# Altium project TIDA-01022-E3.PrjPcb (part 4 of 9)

## Sheet TIDA-01022-E3_LMK00304_Buffer.SchDoc: LMK00304_Buffer
size 431 x 279 mm; Date: Not shown in title block; ApprovedBy: Not shown in title block; CheckedBy: Not shown in title block; Author: Not shown in title block; CompanyName: Not shown in title block; DrawnBy: Avinash N; Engineer: Not shown in title block; Organization: Not shown in title block; Address1: Not shown in title block; Address2: Not shown in title block; Address3: Not shown in title block; Address4: Not shown in title block; DocumentNumber: 1; Revision: Use project parameter SCH_Rev; SheetNumber: 12; SheetTotal: 26; PageSetup: Record=PageOptions¦CenterHorizontal=True¦CenterVertical=True¦PrintScale=1.00¦XCorrection=1.00¦YCorrection=1.00¦PrintKind=0¦BorderSize=5000000¦LeftOffset=0¦BottomOffset=0¦Orientation=2¦PaperLength=1000¦PaperWidth=1000¦Scale=100¦PaperSource=15¦PrintQuality=600¦MediaType=1¦DitherType=10¦PaperKind=Letter¦PrintScaleMode=1

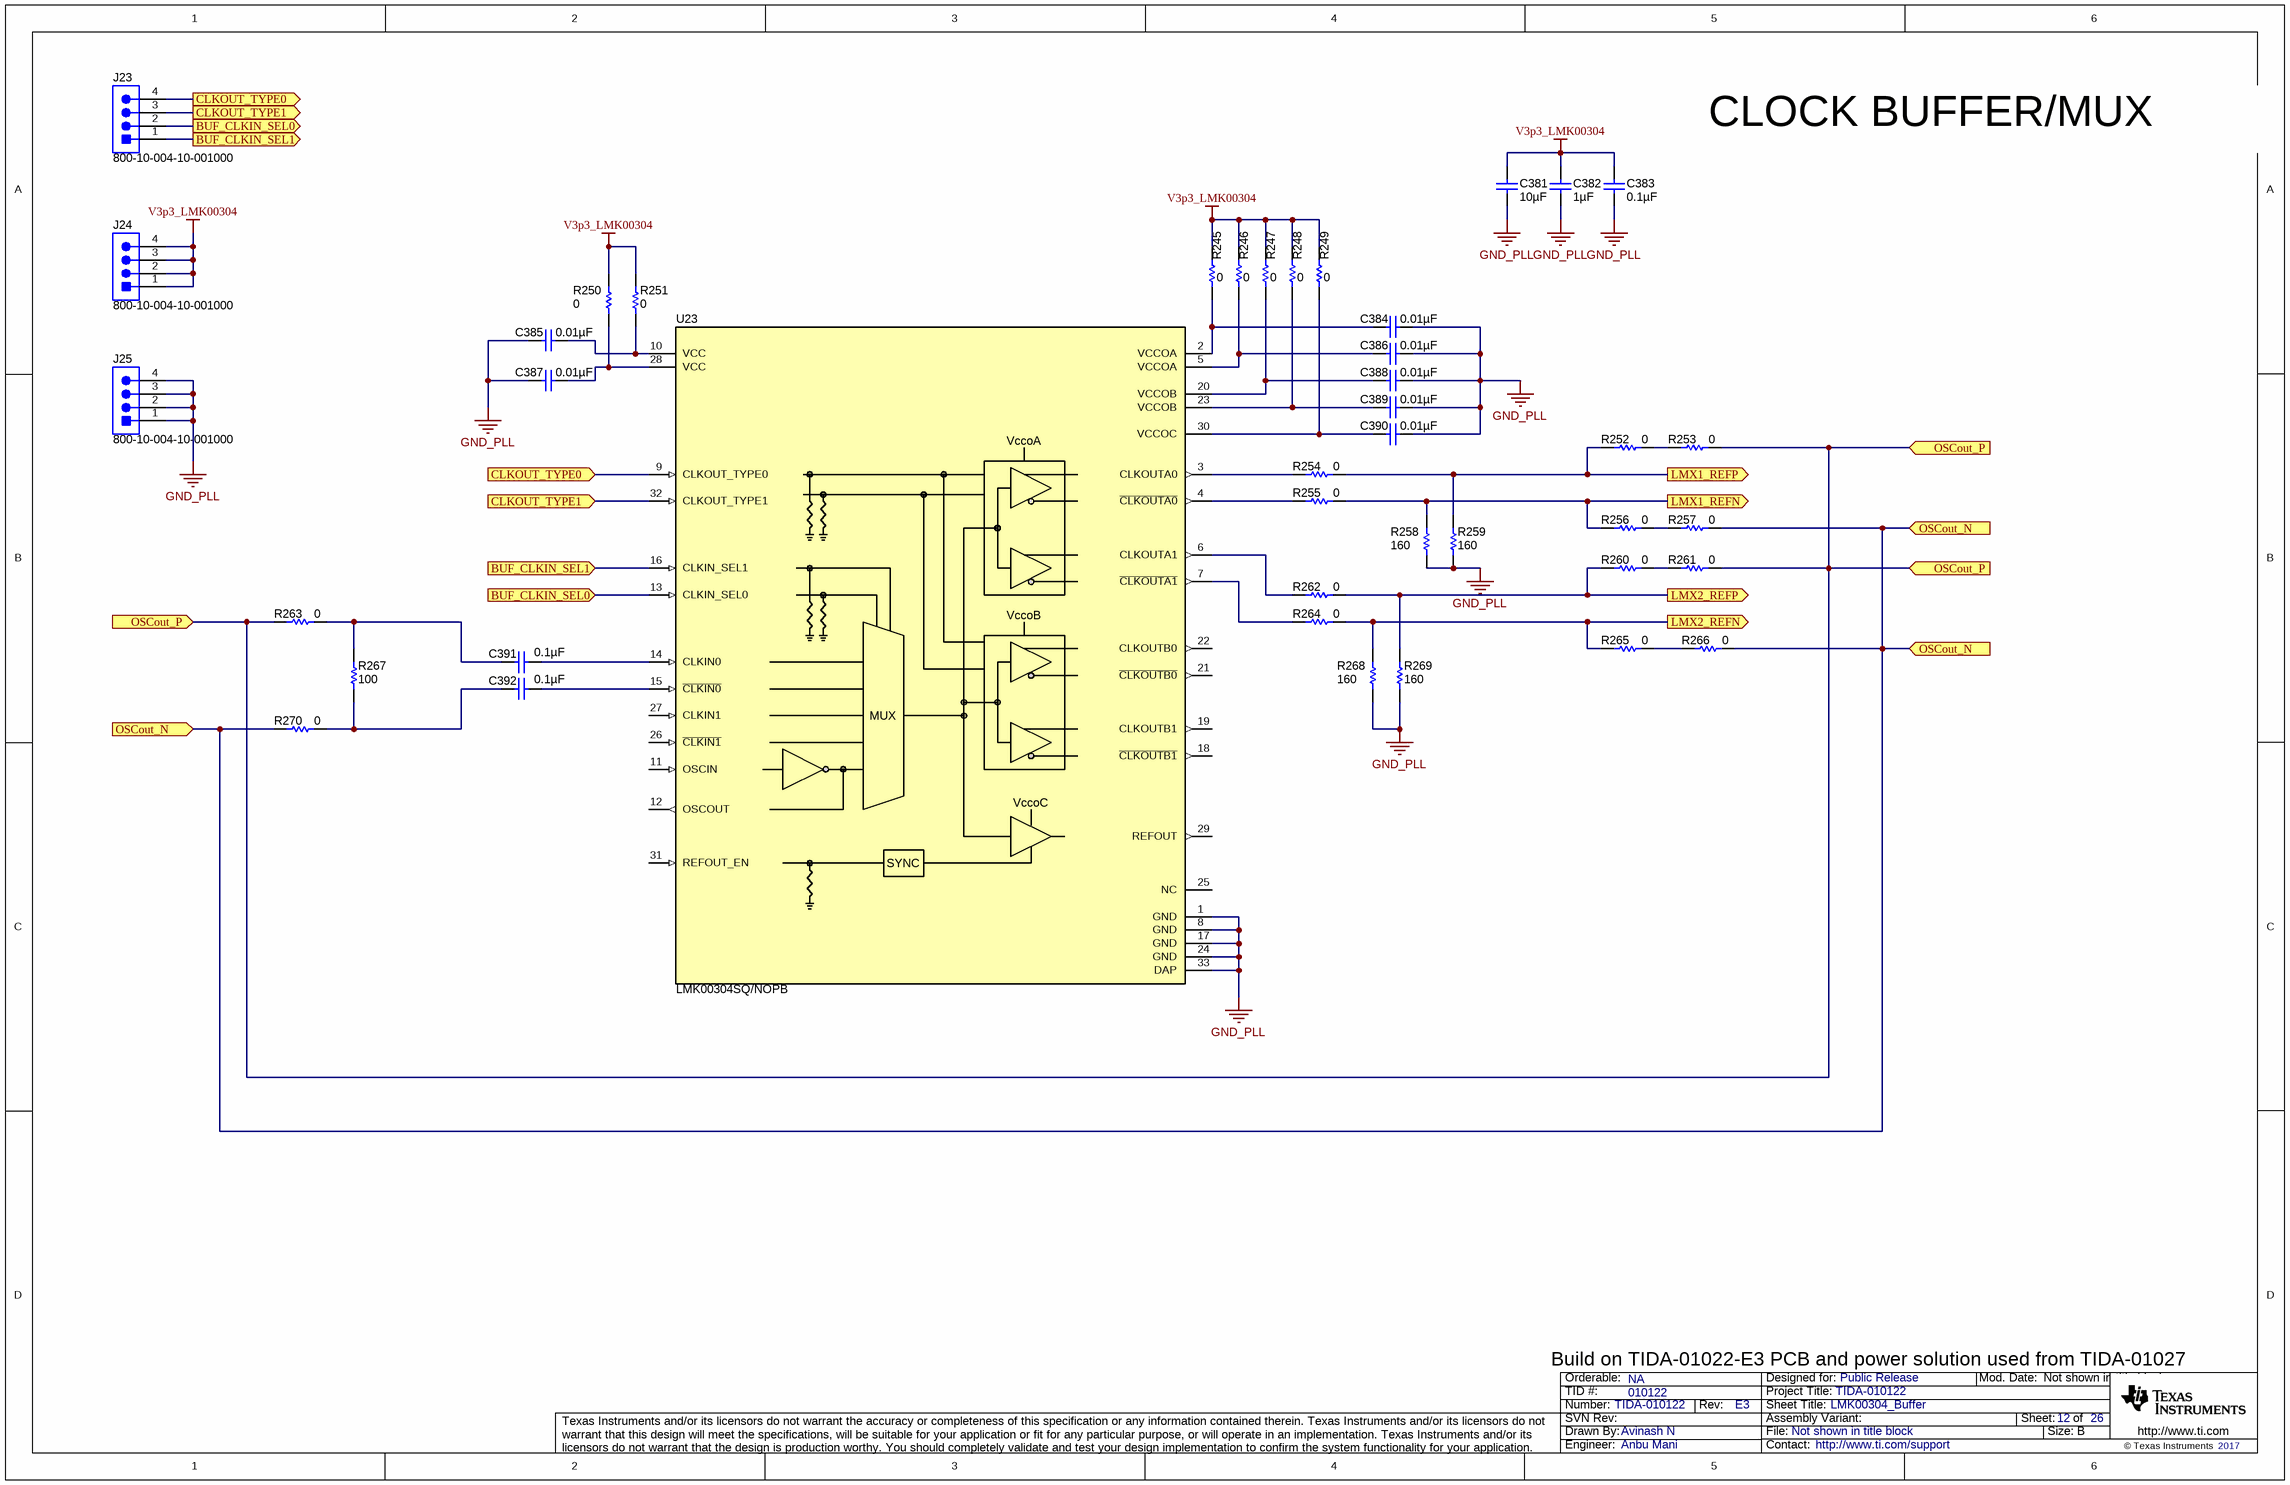
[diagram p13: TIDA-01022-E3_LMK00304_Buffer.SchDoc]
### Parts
C381  ValueDisplayed: 10µF  [0603]  (hidden comment: EMK107BBJ106MA-T)
C382  ValueDisplayed: 1µF  [0402]  (hidden comment: C1005X7S1A105K050BC)
C383  ValueDisplayed: 0.1µF  [0402]  (hidden comment: GRM155R71C104KA88D)
C384  ValueDisplayed: 0.01µF  [0402]  (hidden comment: GRM155R71E103KA01D)
C385  ValueDisplayed: 0.01µF  [0402]  (hidden comment: GRM155R71E103KA01D)
C386  ValueDisplayed: 0.01µF  [0402]  (hidden comment: GRM155R71E103KA01D)
C387  ValueDisplayed: 0.01µF  [0402]  (hidden comment: GRM155R71E103KA01D)
C388  ValueDisplayed: 0.01µF  [0402]  (hidden comment: GRM155R71E103KA01D)
C389  ValueDisplayed: 0.01µF  [0402]  (hidden comment: GRM155R71E103KA01D)
C390  ValueDisplayed: 0.01µF  [0402]  (hidden comment: GRM155R71E103KA01D)
C391  ValueDisplayed: 0.1µF  [0402]  (hidden comment: C1005X7R1E104M050BB)
C392  ValueDisplayed: 0.1µF  [0402]  (hidden comment: C1005X7R1E104M050BB)
J23  800-10-004-10-001000  [Mill-Max_800-10-004-10-001000]
J24  800-10-004-10-001000  [Mill-Max_800-10-004-10-001000]
J25  800-10-004-10-001000  [Mill-Max_800-10-004-10-001000]
R245  ValueDisplayed: 0  [0402]  (hidden comment: CRCW04020000Z0ED)
R246  ValueDisplayed: 0  [0402]  (hidden comment: CRCW04020000Z0ED)
R247  ValueDisplayed: 0  [0402]  (hidden comment: CRCW04020000Z0ED)
R248  ValueDisplayed: 0  [0402]  (hidden comment: CRCW04020000Z0ED)
R249  ValueDisplayed: 0  [0402]  (hidden comment: CRCW04020000Z0ED)
R250  ValueDisplayed: 0  [0402]  (hidden comment: CRCW04020000Z0ED)
R251  ValueDisplayed: 0  [0402]  (hidden comment: CRCW04020000Z0ED)
R252  ValueDisplayed: 0  [0402]  (hidden comment: CRCW04020000Z0ED)
R253  ValueDisplayed: 0  [0402]  (hidden comment: CRCW04020000Z0ED)
R254  ValueDisplayed: 0  [0402]  (hidden comment: CRCW04020000Z0ED)
R255  ValueDisplayed: 0  [0402]  (hidden comment: CRCW04020000Z0ED)
R256  ValueDisplayed: 0  [0402]  (hidden comment: CRCW04020000Z0ED)
R257  ValueDisplayed: 0  [0402]  (hidden comment: CRCW04020000Z0ED)
R258  ValueDisplayed: 160  [0402]  (hidden comment: CRCW0402160RJNED)
R259  ValueDisplayed: 160  [0402]  (hidden comment: CRCW0402160RJNED)
R260  ValueDisplayed: 0  [0402]  (hidden comment: CRCW04020000Z0ED)
R261  ValueDisplayed: 0  [0402]  (hidden comment: CRCW04020000Z0ED)
R262  ValueDisplayed: 0  [0402]  (hidden comment: CRCW04020000Z0ED)
R263  ValueDisplayed: 0  [0402]  (hidden comment: CRCW04020000Z0ED)
R264  ValueDisplayed: 0  [0402]  (hidden comment: CRCW04020000Z0ED)
R265  ValueDisplayed: 0  [0402]  (hidden comment: CRCW04020000Z0ED)
R266  ValueDisplayed: 0  [0402]  (hidden comment: CRCW04020000Z0ED)
R267  ValueDisplayed: 100  [0402]  (hidden comment: CRCW0402100RFKED)
R268  ValueDisplayed: 160  [0402]  (hidden comment: CRCW0402160RJNED)
R269  ValueDisplayed: 160  [0402]  (hidden comment: CRCW0402160RJNED)
R270  ValueDisplayed: 0  [0402]  (hidden comment: CRCW04020000Z0ED)
U23  LMK00304SQ/NOPB  [RTV0032A]

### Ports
BUF_CLKIN_SEL0 (in), BUF_CLKIN_SEL0 (out), BUF_CLKIN_SEL1 (in), BUF_CLKIN_SEL1 (out), CLKOUT_TYPE0 (in), CLKOUT_TYPE0 (out), CLKOUT_TYPE1 (in), CLKOUT_TYPE1 (out), LMX1_REFN (out), LMX1_REFP (out), LMX2_REFN (out), LMX2_REFP (out), OSCout_N (in), OSCout_P (in)

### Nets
GND_PLL: C381.2 C382.2 C383.2 C384.2 C385.1 C386.2 C387.1 C388.2 C389.2 C390.2 J25.1 J25.2 J25.3 J25.4 R258.1 R259.1 R268.1 R269.1 U23.1(GND) U23.8(GND) U23.17(GND) U23.24(GND) U23.33(DAP)  [project net DGND]
V3p3_LMK00304: C381.1 C382.1 C383.1 J24.1 J24.2 J24.3 J24.4 R245.2 R246.2 R247.2 R248.2 R249.2 R250.2 R251.2
BUF_CLKIN_SEL0: J23.2 U23.13(CLKIN_SEL0) ; port BUF_CLKIN_SEL0
BUF_CLKIN_SEL1: J23.1 U23.16(CLKIN_SEL1) ; port BUF_CLKIN_SEL1
CLKOUT_TYPE0: J23.4 U23.9(CLKOUT_TYPE0) ; port CLKOUT_TYPE0
CLKOUT_TYPE1: J23.3 U23.32(CLKOUT_TYPE1) ; port CLKOUT_TYPE1
LMX1_REFN: R255.2 R256.1 R258.2 ; port LMX1_REFN
LMX1_REFP: R252.1 R254.2 R259.2 ; port LMX1_REFP
LMX2_REFN: R264.2 R265.1 R268.2 ; port LMX2_REFN
LMX2_REFP: R260.1 R262.2 R269.2 ; port LMX2_REFP
OSCout_N: R257.2 R266.2 R270.1 ; port OSCout_N
OSCout_P: R253.2 R261.2 R263.1 ; port OSCout_P
NetC384_1: C384.1 R245.1 U23.2(VCCOA)
NetC385_2: C385.2 R251.1 U23.10(VCC)
NetC386_1: C386.1 R246.1 U23.5(VCCOA)
NetC387_2: C387.2 R250.1 U23.28(VCC)
NetC388_1: C388.1 R247.1 U23.20(VCCOB)
NetC389_1: C389.1 R248.1 U23.23(VCCOB)
NetC390_1: C390.1 R249.1 U23.30(VCCOC)
NetC391_1: C391.1 R263.2 R267.2
NetC391_2: C391.2 U23.14(CLKIN0)
NetC392_1: C392.1 R267.1 R270.2
NetC392_2: C392.2 U23.15(~{CLKIN0})
NetR252_2: R252.2 R253.1
NetR254_1: R254.1 U23.3(CLKOUTA0)
NetR255_1: R255.1 U23.4(~{CLKOUTA0})
NetR256_2: R256.2 R257.1
NetR260_2: R260.2 R261.1
NetR262_1: R262.1 U23.6(CLKOUTA1)
NetR264_1: R264.1 U23.7(~{CLKOUTA1})
NetR265_2: R265.2 R266.1

Not connected (* = marked no-connect by the designer): U23 11(OSCIN) 12(OSCOUT) 18(~{CLKOUTB1}) 19(CLKOUTB1) 21(~{CLKOUTB0}) 22(CLKOUTB0) 25(NC) 26(~{CLKIN1}) 27(CLKIN1) 29(REFOUT) 31(REFOUT_EN)

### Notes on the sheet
- CLOCK BUFFER/MUX
- Build on TIDA-01022-E3 PCB and power solution used from TIDA-01027

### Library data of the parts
C381 = EMK107BBJ106MA-T: CAP, CERM, 10 µF, 16 V, +/- 20%, X5R, 0603; Manufacturer: Taiyo Yuden; Polarized: N; CompType: Capacitor; Value: 10uF; U/M: EA; Cap_F: 0.00001; Tolerance_%: 20; Value1: Unknown; VDC_V: 16; Value2: 16V; TaMin_C: -55; TaMax_C: 85; SizeArea_mm2: 1.28; SizeAreaWB_mm2: 4.68; SizeX_mm: 1.6; SizeY_mm: 0.8; SizeZ_mm: 1; AEC Category: Q200
C382 = C1005X7S1A105K050BC: CAP, CERM, 1 µF, 10 V, +/- 10%, X7S, 0402; Manufacturer: TDK; Polarized: N; CompType: Capacitor; Value: 1uF; U/M: EA; Cap_F: 0.000001; Tolerance_%: 10; ESR_ohm: 0.011416; Value1: 0.011416 ohm; Value2: 10V; IRMS_A: 1.483; TaMin_C: -55; TaMax_C: 125; SizeArea_mm2: 0.5; SizeAreaWB_mm2: 3; SizeX_mm: 1; SizeZ_mm: 0.6; AEC Category: Q200
C383 = GRM155R71C104KA88D: CAP, CERM, 0.1 µF, 16 V, +/- 10%, X7R, 0402; Manufacturer: MuRata; Polarized: N; CompType: Capacitor; Value: 0.1uF; U/M: EA; Cap_F: 0.0000001; Tolerance_%: 10; Value1: Unknown; VDC_V: 16; Value2: 16V; TaMin_C: -55; TaMax_C: 125; SizeArea_mm2: 0.5; SizeAreaWB_mm2: 3; SizeX_mm: 1; SizeZ_mm: 0.6; AEC Category: Q200
C384-C390 = GRM155R71E103KA01D: CAP, CERM, 0.01 µF, 25 V, +/- 10%, X7R, 0402; Manufacturer: MuRata; Polarized: N; CompType: Capacitor; Value: 0.01uF; U/M: EA; Cap_F: 0.00000001; Tolerance_%: 10; Value1: Unknown; VDC_V: 25; Value2: 25V; TaMin_C: -55; TaMax_C: 125; SizeArea_mm2: 0.5; SizeAreaWB_mm2: 3; SizeX_mm: 1; SizeZ_mm: 0.6; AEC Category: Q200
C391 C392 = C1005X7R1E104M050BB: CAP, CERM, 0.1 µF, 25 V, +/- 20%, X7R, 0402; Manufacturer: TDK; Polarized: N; TaMax_C: 125; TaMin_C: -55; Tolerance_%: 20; VDC_V: 25; Cap_F: 0.0000001; CompType: Capacitor; Value: 0.1uF; Value1: Unknown; Value2: 25V; U/M: EA; SizeArea_mm2: 0.5; SizeAreaWB_mm2: 3; SizeX_mm: 1; SizeZ_mm: 0.6; AEC Category: Q200
J23-J25 = 800-10-004-10-001000: Header, 100mil, 4x1, TH; Manufacturer: Mill-Max; SymbolCreator: a0412235
R245-R257 R260-R266 R270 = CRCW04020000Z0ED: RES, 0, 5%, 0.063 W, 0402; Manufacturer: Vishay-Dale; CompType: Resistor; Value: 0; Value_Code: 0000; Tolerance_%: 5; Power_W: 0.063; Value2: 0.063W; VDC_V: 50; TempCo: 200 ppm/C; SizeArea_mm2: 0.5; SizeX_mm: 1; SizeZ_mm: 0.6; EIA_Code: E24; U/M: EA; AEC Category: Q200
R258 R259 R268 R269 = CRCW0402160RJNED: RES, 160, 5%, 0.063 W, 0402; Manufacturer: Vishay-Dale; CompType: Resistor; Value: 160; Value_Code: 160R; Tolerance_%: 5; Power_W: 0.063; Value2: 0.063W; VDC_V: 50; TempCo: 200 ppm/C; SizeArea_mm2: 0.5; SizeX_mm: 1; SizeZ_mm: 0.6; EIA_Code: E24; U/M: EA; AEC Category: Q200
R267 = CRCW0402100RFKED: RES, 100, 1%, 0.063 W, 0402; Manufacturer: Vishay-Dale; CompType: Resistor; Value: 100; Value_Code: 100R; Tolerance_%: 1; Power_W: 0.063; Value2: 0.063W; VDC_V: 50; TempCo: 100 ppm/C; SizeArea_mm2: 0.5; SizeZ_mm: 0.6; EIA_Code: E96; U/M: EA; AEC Category: Q200
U23 = LMK00304SQ/NOPB: 3.1-GHz Differential Clock Buffer/Level Translator, RTV0032A (WQFN-32); Manufacturer: Texas Instruments; SymbolCreator: a0411947; SizeArea_mm2: 25; SizeAreaWB_mm2: 49; SizeX_mm: 5; SizeZ_mm: 0.8; CompType: IC; U/M: EA

## Sheet TIDA-01022-E3_LMK0482x.SchDoc: LMK0482x
size 431 x 279 mm; Date: Not shown in title block; ApprovedBy: Not shown in title block; CheckedBy: Not shown in title block; Author: Not shown in title block; CompanyName: Not shown in title block; DrawnBy: Avinash N; Engineer: Not shown in title block; Organization: Not shown in title block; Address1: Not shown in title block; Address2: Not shown in title block; Address3: Not shown in title block; Address4: Not shown in title block; DocumentNumber: 1; Revision: Use project parameter SCH_Rev; SheetNumber: 13; SheetTotal: 26; PageSetup: Record=PageOptions¦CenterHorizontal=True¦CenterVertical=True¦PrintScale=1.00¦XCorrection=1.00¦YCorrection=1.00¦PrintKind=0¦BorderSize=5000000¦LeftOffset=0¦BottomOffset=0¦Orientation=2¦PaperLength=1000¦PaperWidth=1000¦Scale=100¦PaperSource=15¦PrintQuality=600¦MediaType=1¦DitherType=10¦PaperKind=Letter¦PrintScaleMode=1

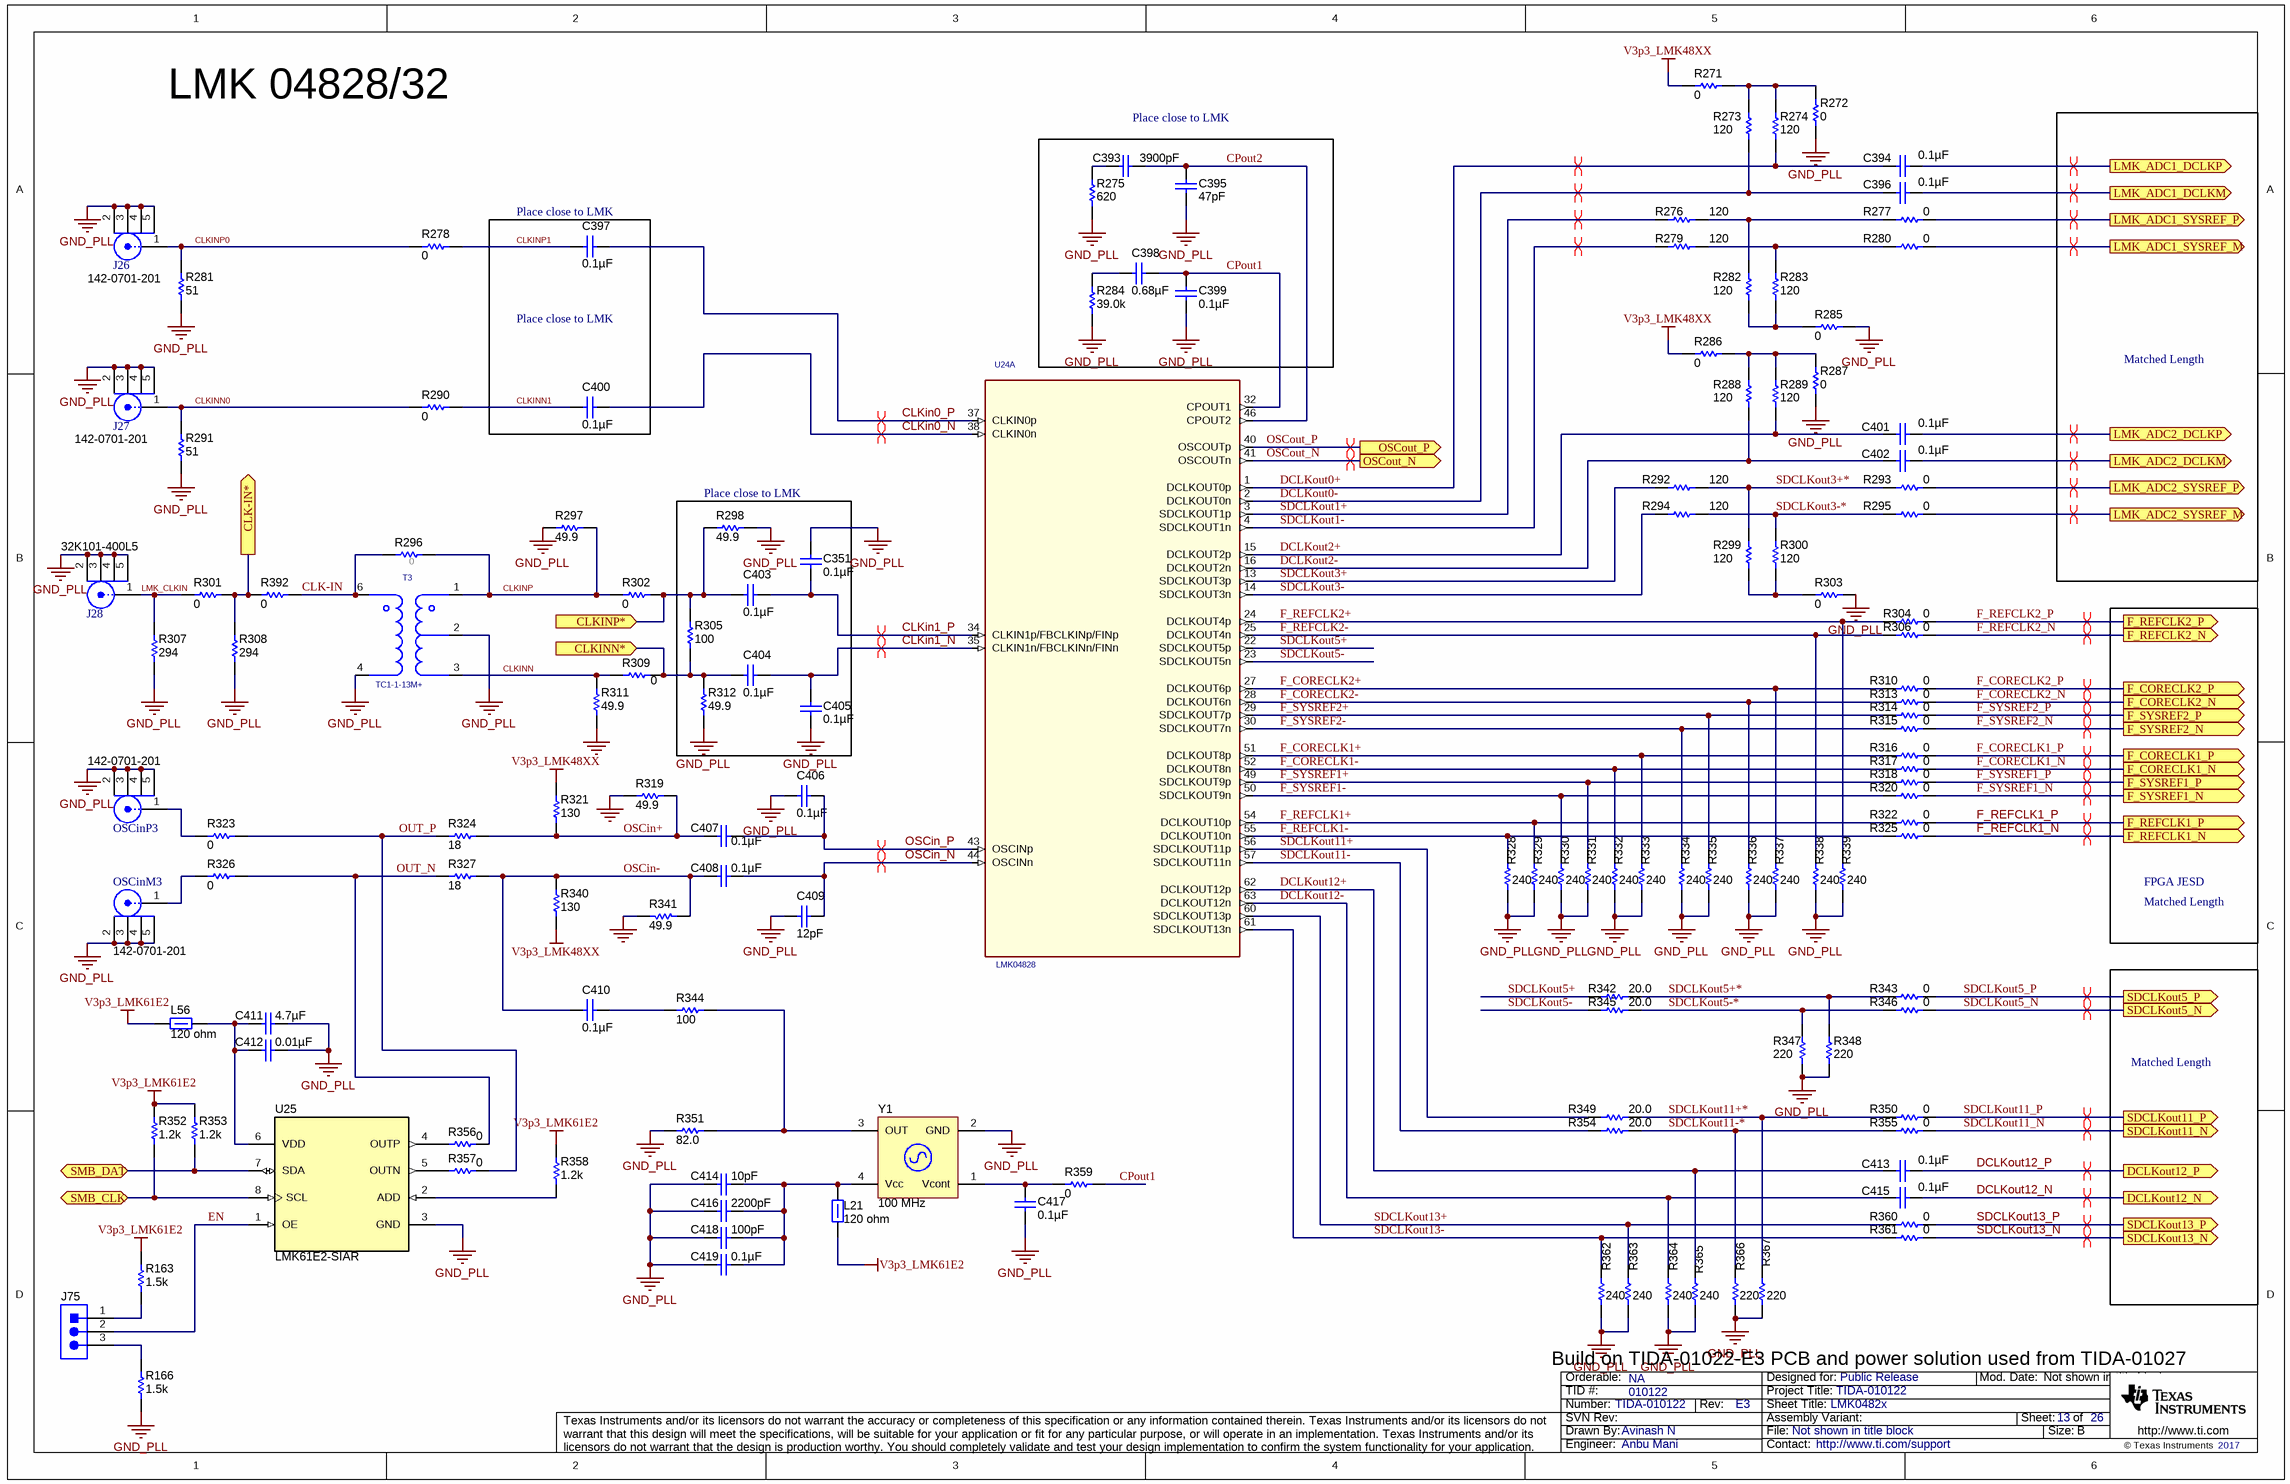
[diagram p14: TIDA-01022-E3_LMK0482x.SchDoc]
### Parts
C351  ValueDisplayed: 0.1µF  [0201_033]  (hidden comment: GRM033R60J104KE19D)
C393  ValueDisplayed: 3900pF  [0201]  (hidden comment: 0201ZD392KAT2A)
C394  ValueDisplayed: 0.1µF  [0402]  (hidden comment: C1005X7R1E104M050BB)
C395  ValueDisplayed: 47pF  [0201_033]  (hidden comment: GRM0335C1E470JA01D)
C396  ValueDisplayed: 0.1µF  [0402]  (hidden comment: C1005X7R1E104M050BB)
C397  ValueDisplayed: 0.1µF  [0201_033]  (hidden comment: GRM033R60J104KE19D)
C398  ValueDisplayed: 0.68µF  [0402]  (hidden comment: C1005X5R1A684K050BB)
C399  ValueDisplayed: 0.1µF  [0402]  (hidden comment: C1005X7R1E104M050BB)
C400  ValueDisplayed: 0.1µF  [0201_033]  (hidden comment: GRM033R60J104KE19D)
C401  ValueDisplayed: 0.1µF  [0402]  (hidden comment: C1005X7R1E104M050BB)
C402  ValueDisplayed: 0.1µF  [0402]  (hidden comment: C1005X7R1E104M050BB)
C403  ValueDisplayed: 0.1µF  [0201_033]  (hidden comment: GRM033R60J104KE19D)
C404  ValueDisplayed: 0.1µF  [0201_033]  (hidden comment: GRM033R60J104KE19D)
C405  ValueDisplayed: 0.1µF  [0201_033]  (hidden comment: GRM033R60J104KE19D)
C406  ValueDisplayed: 0.1µF  [0402]  (hidden comment: C1005X7R1E104M050BB)
C407  ValueDisplayed: 0.1µF  [0402]  (hidden comment: C1005X7R1E104M050BB)
C408  ValueDisplayed: 0.1µF  [0402]  (hidden comment: C1005X7R1E104M050BB)
C409  ValueDisplayed: 12pF  [0402]  (hidden comment: C0402C120J3GACAUTO)
C410  ValueDisplayed: 0.1µF  [0402]  (hidden comment: C1005X7R1E104M050BB)
C411  ValueDisplayed: 4.7µF  [0402]  (hidden comment: C1005X5R0J475M050BC)
C412  ValueDisplayed: 0.01µF  [0402]  (hidden comment: GRM155R71E103KA01D)
C413  ValueDisplayed: 0.1µF  [0402]  (hidden comment: C1005X7R1E104M050BB)
C414  ValueDisplayed: 10pF  [0402]  (hidden comment: GRM1555C1H100JA01D)
C415  ValueDisplayed: 0.1µF  [0402]  (hidden comment: C1005X7R1E104M050BB)
C416  ValueDisplayed: 2200pF  [0402]  (hidden comment: GRM155R71E222KA01D)
C417  ValueDisplayed: 0.1µF  [0402]  (hidden comment: C1005X7R1E104M050BB)
C418  ValueDisplayed: 100pF  [0402]  (hidden comment: 04025A101FAT2A)
C419  ValueDisplayed: 0.1µF  [0402]  (hidden comment: C1005X7R1E104M050BB)
J26  142-0701-201  [Johnson_142-0701-20x]
J27  142-0701-201  [Johnson_142-0701-20x]
J28  32K101-400L5  [Rosenberger_32K101-400L5]
J75  800-10-003-10-001000  [Mill-Max_800-10-003-10-001000]  (value not drawn)
L21  ValueDisplayed: 120 ohm  [0603]  (hidden comment: BLM18SG121TN1D)
L56  ValueDisplayed: 120 ohm  [0603]  (hidden comment: BLM18SG121TN1D)
OSCinM3  142-0701-201  [Johnson_142-0701-20x]
OSCinP3  142-0701-201  [Johnson_142-0701-20x]
R163  ValueDisplayed: 1.5k  [0402]  (hidden comment: CRCW04021K50JNED)
R166  ValueDisplayed: 1.5k  [0402]  (hidden comment: CRCW04021K50JNED)
R271  ValueDisplayed: 0  [0402]  (hidden comment: CRCW04020000Z0ED)
R272  ValueDisplayed: 0  [0402]  (hidden comment: CRCW04020000Z0ED)
R273  ValueDisplayed: 120  [0402]  (hidden comment: CRCW0402120RJNED)
R274  ValueDisplayed: 120  [0402]  (hidden comment: CRCW0402120RJNED)
R275  ValueDisplayed: 620  [0201]  (hidden comment: RC0201FR-07620RL)
R276  ValueDisplayed: 120  [0402]  (hidden comment: CRCW0402120RJNED)
R277  ValueDisplayed: 0  [0402]  (hidden comment: CRCW04020000Z0ED)
R278  ValueDisplayed: 0  [0201]  (hidden comment: CRCW02010000Z0ED)
R279  ValueDisplayed: 120  [0402]  (hidden comment: CRCW0402120RJNED)
R280  ValueDisplayed: 0  [0402]  (hidden comment: CRCW04020000Z0ED)
R281  ValueDisplayed: 51  [0201]  (hidden comment: RC0201JR-0751RL)
R282  ValueDisplayed: 120  [0402]  (hidden comment: CRCW0402120RJNED)
R283  ValueDisplayed: 120  [0402]  (hidden comment: CRCW0402120RJNED)
R284  ValueDisplayed: 39.0k  [0201]  (hidden comment: RC0201FR-0739KL)
R285  ValueDisplayed: 0  [0402]  (hidden comment: CRCW04020000Z0ED)
R286  ValueDisplayed: 0  [0402]  (hidden comment: CRCW04020000Z0ED)
R287  ValueDisplayed: 0  [0402]  (hidden comment: CRCW04020000Z0ED)
R288  ValueDisplayed: 120  [0402]  (hidden comment: CRCW0402120RJNED)
R289  ValueDisplayed: 120  [0402]  (hidden comment: CRCW0402120RJNED)
R290  ValueDisplayed: 0  [0201]  (hidden comment: CRCW02010000Z0ED)
R291  ValueDisplayed: 51  [0201]  (hidden comment: RC0201JR-0751RL)
R292  ValueDisplayed: 120  [0402]  (hidden comment: CRCW0402120RJNED)
R293  ValueDisplayed: 0  [0402]  (hidden comment: CRCW04020000Z0ED)
R294  ValueDisplayed: 120  [0402]  (hidden comment: CRCW0402120RJNED)
R295  ValueDisplayed: 0  [0402]  (hidden comment: CRCW04020000Z0ED)
R296  ValueDisplayed: 0  [0603]  (hidden comment: CRCW06030000Z0EA)
R297  ValueDisplayed: 49.9  [0201]  (hidden comment: CRCW020149R9FKED)
R298  ValueDisplayed: 49.9  [0201]  (hidden comment: CRCW020149R9FKED)
R299  ValueDisplayed: 120  [0402]  (hidden comment: CRCW0402120RJNED)
R300  ValueDisplayed: 120  [0402]  (hidden comment: CRCW0402120RJNED)
R301  ValueDisplayed: 0  [0201_adc]  (hidden comment: CRCW02010000Z0ED)
R302  ValueDisplayed: 0  [0201]  (hidden comment: CRCW02010000Z0ED)
R303  ValueDisplayed: 0  [0402]  (hidden comment: CRCW04020000Z0ED)
R304  ValueDisplayed: 0  [0402]  (hidden comment: CRCW04020000Z0ED)
R305  ValueDisplayed: 100  [0201]  (hidden comment: ERJ-1GEF1000C)
R306  ValueDisplayed: 0  [0402]  (hidden comment: CRCW04020000Z0ED)
R307  ValueDisplayed: 294  [0201_adc]  (hidden comment: RC0201FR-07294RL)
R308  ValueDisplayed: 294  [0201_adc]  (hidden comment: RC0201FR-07294RL)
R309  ValueDisplayed: 0  [0201]  (hidden comment: CRCW02010000Z0ED)
R310  ValueDisplayed: 0  [0402]  (hidden comment: CRCW04020000Z0ED)
R311  ValueDisplayed: 49.9  [0201]  (hidden comment: CRCW020149R9FKED)
R312  ValueDisplayed: 49.9  [0201]  (hidden comment: CRCW020149R9FKED)
R313  ValueDisplayed: 0  [0402]  (hidden comment: CRCW04020000Z0ED)
R314  ValueDisplayed: 0  [0402]  (hidden comment: CRCW04020000Z0ED)
R315  ValueDisplayed: 0  [0402]  (hidden comment: CRCW04020000Z0ED)
R316  ValueDisplayed: 0  [0402]  (hidden comment: CRCW04020000Z0ED)
R317  ValueDisplayed: 0  [0402]  (hidden comment: CRCW04020000Z0ED)
R318  ValueDisplayed: 0  [0402]  (hidden comment: CRCW04020000Z0ED)
R319  ValueDisplayed: 49.9  [0402]  (hidden comment: CRCW040249R9FKED)
R320  ValueDisplayed: 0  [0402]  (hidden comment: CRCW04020000Z0ED)
R321  ValueDisplayed: 130  [0402]  (hidden comment: CRCW0402130RFKED)
R322  ValueDisplayed: 0  [0402]  (hidden comment: CRCW04020000Z0ED)
R323  ValueDisplayed: 0  [0402]  (hidden comment: CRCW04020000Z0ED)
R324  ValueDisplayed: 18  [0402]  (hidden comment: CRCW040218R0JNED)
R325  ValueDisplayed: 0  [0402]  (hidden comment: CRCW04020000Z0ED)
R326  ValueDisplayed: 0  [0402]  (hidden comment: CRCW04020000Z0ED)
R327  ValueDisplayed: 18  [0402]  (hidden comment: CRCW040218R0JNED)
R328  ValueDisplayed: 240  [0402]  (hidden comment: CRCW0402240RJNED)
R329  ValueDisplayed: 240  [0402]  (hidden comment: CRCW0402240RJNED)
R330  ValueDisplayed: 240  [0402]  (hidden comment: CRCW0402240RJNED)
R331  ValueDisplayed: 240  [0402]  (hidden comment: CRCW0402240RJNED)
R332  ValueDisplayed: 240  [0402]  (hidden comment: CRCW0402240RJNED)
R333  ValueDisplayed: 240  [0402]  (hidden comment: CRCW0402240RJNED)
R334  ValueDisplayed: 240  [0402]  (hidden comment: CRCW0402240RJNED)
R335  ValueDisplayed: 240  [0402]  (hidden comment: CRCW0402240RJNED)
R336  ValueDisplayed: 240  [0402]  (hidden comment: CRCW0402240RJNED)
R337  ValueDisplayed: 240  [0402]  (hidden comment: CRCW0402240RJNED)
R338  ValueDisplayed: 240  [0402]  (hidden comment: CRCW0402240RJNED)
R339  ValueDisplayed: 240  [0402]  (hidden comment: CRCW0402240RJNED)
R340  ValueDisplayed: 130  [0402]  (hidden comment: CRCW0402130RFKED)
R341  ValueDisplayed: 49.9  [0402]  (hidden comment: CRCW040249R9FKED)
R342  ValueDisplayed: 20.0  [0402]  (hidden comment: CRCW040220R0FKED)
R343  ValueDisplayed: 0  [0402]  (hidden comment: CRCW04020000Z0ED)
R344  ValueDisplayed: 100  [0402]  (hidden comment: CRCW0402100RFKED)
R345  ValueDisplayed: 20.0  [0402]  (hidden comment: CRCW040220R0FKED)
R346  ValueDisplayed: 0  [0402]  (hidden comment: CRCW04020000Z0ED)
R347  ValueDisplayed: 220  [0402]  (hidden comment: CRCW0402220RJNED)
R348  ValueDisplayed: 220  [0402]  (hidden comment: CRCW0402220RJNED)
R349  ValueDisplayed: 20.0  [0402]  (hidden comment: CRCW040220R0FKED)
R350  ValueDisplayed: 0  [0402]  (hidden comment: CRCW04020000Z0ED)
R351  ValueDisplayed: 82.0  [0603]  (hidden comment: RC0603FR-0782RL)
R352  ValueDisplayed: 1.2k  [0402]  (hidden comment: CRCW04021K20JNED)
R353  ValueDisplayed: 1.2k  [0402]  (hidden comment: CRCW04021K20JNED)
R354  ValueDisplayed: 20.0  [0402]  (hidden comment: CRCW040220R0FKED)
R355  ValueDisplayed: 0  [0402]  (hidden comment: CRCW04020000Z0ED)
R356  ValueDisplayed: 0  [0402]  (hidden comment: CRCW04020000Z0ED)
R357  ValueDisplayed: 0  [0402]  (hidden comment: CRCW04020000Z0ED)
R358  ValueDisplayed: 1.2k  [0402]  (hidden comment: CRCW04021K20JNED)
R359  ValueDisplayed: 0  [0402]  (hidden comment: CRCW04020000Z0ED)
R360  ValueDisplayed: 0  [0402]  (hidden comment: CRCW04020000Z0ED)
R361  ValueDisplayed: 0  [0402]  (hidden comment: CRCW04020000Z0ED)
R362  ValueDisplayed: 240  [0402]  (hidden comment: CRCW0402240RJNED)
R363  ValueDisplayed: 240  [0402]  (hidden comment: CRCW0402240RJNED)
R364  ValueDisplayed: 240  [0402]  (hidden comment: CRCW0402240RJNED)
R365  ValueDisplayed: 240  [0402]  (hidden comment: CRCW0402240RJNED)
R366  ValueDisplayed: 220  [0402]  (hidden comment: CRCW0402220RJNED)
R367  ValueDisplayed: 220  [0402]  (hidden comment: CRCW0402220RJNED)
R392  ValueDisplayed: 0  [0201_ADC]  (hidden comment: CRCW02010000Z0ED)
T3  TC1-1-13M+  [TFMR_5_150x150_50]
U24  LMK04828  [NKD0064A]  (part A of 2)
U25  LMK61E2-SIAR  [SIA0008B]
Y1  Frequency: 100 MHz  [OSC_CVHD-950-4]  (hidden comment: CVHD-950-100.000)

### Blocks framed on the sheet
Place close to LMK: C393 C395 C398 C399 R275 R284
Place close to LMK: C351 C403-C405 R298 R305 R312

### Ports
CLK-IN* (out), CLKINN* (in), CLKINP* (in), DCLKout12_N (out), DCLKout12_P (out), F_CORECLK1_N (out), F_CORECLK1_P (out), F_CORECLK2_N (out), F_CORECLK2_P (out), F_REFCLK1_N (out), F_REFCLK1_P (out), F_REFCLK2_N (out), F_REFCLK2_P (out), F_SYSREF1_N (out), F_SYSREF1_P (out), F_SYSREF2_N (out), F_SYSREF2_P (out), LMK_ADC1_DCLKM (out), LMK_ADC1_DCLKP (out), LMK_ADC1_SYSREF_M (out), LMK_ADC1_SYSREF_P (out), LMK_ADC2_DCLKM (out), LMK_ADC2_DCLKP (out), LMK_ADC2_SYSREF_M (out), LMK_ADC2_SYSREF_P (out), OSCout_N (out), OSCout_P (out), SDCLKout5_N (out), SDCLKout5_P (out), SDCLKout11_N (out), SDCLKout11_P (out), SDCLKout13_N (out), SDCLKout13_P (out), SMB_CLK (bidir), SMB_DAT (bidir)

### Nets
GND_PLL: C351.1 C395.2 C399.1 C405.1 C406.1 C409.1 C411.1 C412.1 C414.1 C416.1 C417.1 C418.1 C419.1 J26.2 J26.3 J26.4 J26.5 J27.2 J27.3 J27.4 J27.5 J28.2 J28.3 J28.4 J28.5 OSCinM3.2 OSCinM3.3 OSCinM3.4 OSCinM3.5 OSCinP3.2 OSCinP3.3 OSCinP3.4 OSCinP3.5 R166.1 R272.1 R275.1 R281.1 R284.1 R285.2 R287.1 R291.1 R297.1 R298.2 R303.2 R307.1 R308.1 R311.1 R312.1 R319.1 R328.1 R329.1 R330.1 R331.1 R332.1 R333.1 R334.1 R335.1 R336.1 R337.1 R338.1 R339.1 R341.1 R347.1 R348.1 R351.1 R362.1 R363.1 R364.1 R365.1 R366.1 R367.1 T3.2(secondary_ct) T3.4(primary) U25.3(GND) Y1.2(GND)  [project net DGND]
V3p3_LMK48XX: R271.2 R286.2 R321.1 R340.1
V3p3_LMK61E2: L21.2 L56.1 R163.2 R352.2 R353.2 R358.1
CLK-IN: R296.1 R392.2 T3.6(primary_dot)
CLK-IN*: R301.2 R308.2 R392.1 ; port CLK-IN*
CLKin0_N: C400.2 U24.38(CLKIN0n)
CLKin0_P: C397.2 U24.37(CLKIN0p)
CLKin1_N: C404.2 C405.2 U24.35(CLKIN1n/FBCLKINn/FINn)
CLKin1_P: C351.2 C403.2 U24.34(CLKIN1p/FBCLKINp/FINp)
CLKINN: R309.1 R311.2 T3.3(secondary)
CLKINN0: J27.1 R290.1 R291.2
CLKINN1: C400.1 R290.2
CLKINN*: C404.1 R305.1 R309.2 R312.2 ; port CLKINN*
CLKINP: R296.2 R297.2 R302.1 T3.1(secondary_dot)
CLKINP0: J26.1 R278.1 R281.2
CLKINP1: C397.1 R278.2
CLKINP*: C403.1 R298.1 R302.2 R305.2 ; port CLKINP*
CPout1: C398.2 C399.2 R359.2 U24.32(CPOUT1)
CPout2: C393.1 C395.1 U24.46(CPOUT2)
DCLKout0+: C394.1 R274.2 U24.1(DCLKOUT0p)
DCLKout0-: C396.1 R273.2 U24.2(DCLKOUT0n)
DCLKout2+: C401.1 R289.2 U24.15(DCLKOUT2p)
DCLKout2-: C402.1 R288.2 U24.16(DCLKOUT2n)
DCLKout12+: C413.1 R365.2 U24.62(DCLKOUT12p)
DCLKout12-: C415.1 R364.2 U24.63(DCLKOUT12n)
DCLKout12_N: C415.2 ; port DCLKout12_N
DCLKout12_P: C413.2 ; port DCLKout12_P
EN: J75.2 U25.1(OE)
F_CORECLK1+: R316.1 R333.2 U24.51(DCLKOUT8p)
F_CORECLK1-: R317.1 R332.2 U24.52(DCLKOUT8n)
F_CORECLK1_N: R317.2 ; port F_CORECLK1_N
F_CORECLK1_P: R316.2 ; port F_CORECLK1_P
F_CORECLK2+: R310.1 R337.2 U24.27(DCLKOUT6p)
F_CORECLK2-: R313.1 R336.2 U24.28(DCLKOUT6n)
F_CORECLK2_N: R313.2 ; port F_CORECLK2_N
F_CORECLK2_P: R310.2 ; port F_CORECLK2_P
F_REFCLK1+: R322.1 R329.2 U24.54(DCLKOUT10p)
F_REFCLK1-: R325.1 R328.2 U24.55(DCLKOUT10n)
F_REFCLK1_N: R325.2 ; port F_REFCLK1_N
F_REFCLK1_P: R322.2 ; port F_REFCLK1_P
F_REFCLK2+: R304.1 R339.2 U24.24(DCLKOUT4p)
F_REFCLK2-: R306.1 R338.2 U24.25(DCLKOUT4n)
F_REFCLK2_N: R306.2 ; port F_REFCLK2_N
F_REFCLK2_P: R304.2 ; port F_REFCLK2_P
F_SYSREF1+: R318.1 R331.2 U24.49(SDCLKOUT9p)
F_SYSREF1-: R320.1 R330.2 U24.50(SDCLKOUT9n)
F_SYSREF1_N: R320.2 ; port F_SYSREF1_N
F_SYSREF1_P: R318.2 ; port F_SYSREF1_P
F_SYSREF2+: R314.1 R335.2 U24.29(SDCLKOUT7p)
F_SYSREF2-: R315.1 R334.2 U24.30(SDCLKOUT7n)
F_SYSREF2_N: R315.2 ; port F_SYSREF2_N
F_SYSREF2_P: R314.2 ; port F_SYSREF2_P
LMK_ADC1_DCLKM: C396.2 ; port LMK_ADC1_DCLKM
LMK_ADC1_DCLKP: C394.2 ; port LMK_ADC1_DCLKP
LMK_ADC1_SYSREF_M: R280.2 ; port LMK_ADC1_SYSREF_M
LMK_ADC1_SYSREF_P: R277.2 ; port LMK_ADC1_SYSREF_P
LMK_ADC2_DCLKM: C402.2 ; port LMK_ADC2_DCLKM
LMK_ADC2_DCLKP: C401.2 ; port LMK_ADC2_DCLKP
LMK_ADC2_SYSREF_M: R295.2 ; port LMK_ADC2_SYSREF_M
LMK_ADC2_SYSREF_P: R293.2 ; port LMK_ADC2_SYSREF_P
LMK_CLKIN: J28.1 R301.1 R307.2
OSCin+: C407.2 R319.2 R321.2 R324.2
OSCin-: C408.2 C410.2 R327.2 R340.2 R341.2
OSCin_N: C408.1 C409.2 U24.44(OSCINn)
OSCin_P: C406.2 C407.1 U24.43(OSCINp)
OSCout_N: U24.41(OSCOUTn) ; port OSCout_N
OSCout_P: U24.40(OSCOUTp) ; port OSCout_P
OUT_N: R326.1 R327.1 R356.2
OUT_P: R323.1 R324.1 R357.2
SDCLKout1+: R276.2 U24.3(SDCLKOUT1p)
SDCLKout1-: R279.2 U24.4(SDCLKOUT1n)
SDCLKout3+: R292.2 U24.13(SDCLKOUT3p)
SDCLKout3+*: R292.1 R293.1 R299.2
SDCLKout3-: R294.2 U24.14(SDCLKOUT3n)
SDCLKout3-*: R294.1 R295.1 R300.2
SDCLKout5+: R342.2 U24.22(SDCLKOUT5p)
SDCLKout5+*: R342.1 R343.1 R348.2
SDCLKout5-: R345.2 U24.23(SDCLKOUT5n)
SDCLKout5-*: R345.1 R346.1 R347.2
SDCLKout5_N: R346.2 ; port SDCLKout5_N
SDCLKout5_P: R343.2 ; port SDCLKout5_P
SDCLKout11+: R349.2 U24.56(SDCLKOUT11p)
SDCLKout11+*: R349.1 R350.1 R367.2
SDCLKout11-: R354.2 U24.57(SDCLKOUT11n)
SDCLKout11-*: R354.1 R355.1 R366.2
SDCLKout11_N: R355.2 ; port SDCLKout11_N
SDCLKout11_P: R350.2 ; port SDCLKout11_P
SDCLKout13+: R360.1 R363.2 U24.60(SDCLKOUT13p)
SDCLKout13-: R361.1 R362.2 U24.61(SDCLKOUT13n)
SDCLKout13_N: R361.2 ; port SDCLKout13_N
SDCLKout13_P: R360.2 ; port SDCLKout13_P
SMB_CLK: R352.1 U25.8(SCL) ; port SMB_CLK
SMB_DAT: R353.1 U25.7(SDA) ; port SMB_DAT
NetC393_2: C393.2 R275.2
NetC398_1: C398.1 R284.2
NetC410_1: C410.1 R344.1
NetC411_2: C411.2 C412.2 L56.2 U25.6(VDD)
NetC414_2: C414.2 C416.2 C418.2 C419.2 L21.1 Y1.4(Vcc)
NetC417_2: C417.2 R359.1 Y1.1(Vcont)
NetJ75_1: J75.1 R163.1
NetJ75_3: J75.3 R166.2
NetOSCinM3_1: OSCinM3.1 R326.2
NetOSCinP3_1: OSCinP3.1 R323.2
NetR271_1: R271.1 R272.2 R273.1 R274.1
NetR276_1: R276.1 R277.1 R282.2
NetR279_1: R279.1 R280.1 R283.2
NetR282_1: R282.1 R283.1 R285.1
NetR286_1: R286.1 R287.2 R288.1 R289.1
NetR299_1: R299.1 R300.1 R303.1
NetR344_2: R344.2 R351.2 Y1.3(OUT)
NetR356_1: R356.1 U25.4(OUTP)
NetR357_1: R357.1 U25.5(OUTN)
NetR358_2: R358.2 U25.2(ADD)

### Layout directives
differential pair: CLKin0_N, CLKin0_P, CLKin1_N, CLKin1_P, DCLKout0+, DCLKout0-, DCLKout12_N, DCLKout12_P, F_CORECLK1_N, F_CORECLK1_P, F_CORECLK2_N, F_CORECLK2_P, F_REFCLK1_N, F_REFCLK1_P, F_REFCLK2_N, F_REFCLK2_P, F_SYSREF1_N, F_SYSREF1_P, F_SYSREF2_N, F_SYSREF2_P, LMK_ADC1_DCLKM, LMK_ADC1_DCLKP, LMK_ADC1_SYSREF_M, LMK_ADC1_SYSREF_P, LMK_ADC2_DCLKM, LMK_ADC2_DCLKP, LMK_ADC2_SYSREF_M, LMK_ADC2_SYSREF_P, OSCin_N, OSCin_P, OSCout_N, OSCout_P, SDCLKout1+, SDCLKout1-, SDCLKout5_N, SDCLKout5_P, SDCLKout11_N, SDCLKout11_P, SDCLKout13_N, SDCLKout13_P

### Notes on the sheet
- LMK 04828/32
- (near C397) Place close to LMK
- Place close to LMK
- Matched Length
- FPGA JESD
- Build on TIDA-01022-E3 PCB and power solution used from TIDA-01027

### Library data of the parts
C351 C397 C400 C403-C405 = GRM033R60J104KE19D: CAP, CERM, 0.1 µF, 6.3 V, +/- 10%, X5R, 0201; Manufacturer: MuRata; Polarized: N; CompType: Capacitor; Value: 0.1uF; U/M: EA; Cap_F: 0.0000001; Tolerance_%: 10; Value1: Unknown; VDC_V: 6.3; Value2: 6.3V; TaMin_C: -55; TaMax_C: 85; Cap_Case: 0201; SizeArea_mm2: 0.18; SizeAreaWB_mm2: 2.08; SizeX_mm: 0.6; SizeY_mm: 0.3; SizeZ_mm: 0.33; AEC Category: Q200
C393 = 0201ZD392KAT2A: CAP, CERM, 3900 pF, 10 V, +/- 10%, X5R, 0201; Manufacturer: AVX; Polarized: N; CompType: Capacitor; Value: 3900pF; U/M: EA; Cap_F: 0.0000000039; Tolerance_%: 10; Value1: Unknown; Value2: 10V; TaMin_C: -55; TaMax_C: 85; SizeArea_mm2: 0.18; SizeAreaWB_mm2: 2.08; SizeX_mm: 0.6; SizeY_mm: 0.3; SizeZ_mm: 0.26; AEC Category: Q200
C394 C396 C399 C401 C402 C406-C408 C410 C413 C415 C417 C419 = C1005X7R1E104M050BB: as C391 on sheet TIDA-01022-E3_LMK00304_Buffer
C395 = GRM0335C1E470JA01D: CAP, CERM, 47 pF, 25 V, +/- 5%, C0G/NP0, 0201; Manufacturer: MuRata; Polarized: N; CompType: Capacitor; Value: 47pF; U/M: EA; Cap_F: 0.000000000047; Tolerance_%: 5; Value1: Unknown; VDC_V: 25; Value2: 25V; TaMin_C: -55; TaMax_C: 125; Cap_Case: 0201; SizeArea_mm2: 0.18; SizeAreaWB_mm2: 2.08; SizeX_mm: 0.6; SizeY_mm: 0.3; SizeZ_mm: 0.33; AEC Category: Q200
C398 = C1005X5R1A684K050BB: CAP, CERM, 0.68 µF, 10 V, +/- 10%, X5R, 0402; Manufacturer: TDK; Polarized: N; CompType: Capacitor; Value: 0.68uF; U/M: EA; Cap_F: 0.00000068; Tolerance_%: 10; Value1: Unknown; Value2: 10V; TaMin_C: -55; TaMax_C: 85; SizeArea_mm2: 0.5; SizeAreaWB_mm2: 3; SizeX_mm: 1; SizeZ_mm: 0.6; AEC Category: Q200
C409 = C0402C120J3GACAUTO: CAP, CERM, 12 pF, 25 V, +/- 5%, C0G/NP0, AEC-Q200 Grade 1, 0402; Manufacturer: Kemet; Polarized: N; CompType: Capacitor; Value: 12pF; U/M: EA; Cap_F: 0.000000000012; Tolerance_%: 5; Value1: Unknown; VDC_V: 25; Value2: 25V; TaMin_C: -55; TaMax_C: 125; SizeArea_mm2: 0.5; SizeAreaWB_mm2: 3; SizeX_mm: 1; SizeZ_mm: 0.6; AEC Category: Q200; AEC Qualified: Y
C411 = C1005X5R0J475M050BC: CAP, CERM, 4.7 µF, 6.3 V, +/- 20%, X5R, 0402; Manufacturer: TDK; Polarized: N; CompType: Capacitor; Value: 4.7uF; U/M: EA; Cap_F: 0.0000047; Tolerance_%: 20; Value1: Unknown; VDC_V: 6.3; Value2: 6.3V; TaMin_C: -55; TaMax_C: 85; SizeArea_mm2: 0.5; SizeAreaWB_mm2: 3; SizeX_mm: 1; SizeZ_mm: 0.6; AEC Category: Q200
C412 = GRM155R71E103KA01D: as C384-C390 on sheet TIDA-01022-E3_LMK00304_Buffer
C414 = GRM1555C1H100JA01D: CAP, CERM, 10 pF, 50 V, +/- 5%, C0G/NP0, 0402; Manufacturer: MuRata; Polarized: N; CompType: Capacitor; Value: 10pF; U/M: EA; Cap_F: 0.00000000001; Tolerance_%: 5; Value1: Unknown; VDC_V: 50; Value2: 50V; TaMin_C: -55; TaMax_C: 125; SizeArea_mm2: 0.5; SizeAreaWB_mm2: 3; SizeX_mm: 1; SizeZ_mm: 0.6; AEC Category: Q200
C416 = GRM155R71E222KA01D: CAP, CERM, 2200 pF, 25 V, +/- 10%, X7R, 0402; Manufacturer: MuRata; Polarized: N; CompType: Capacitor; Value: 2200pF; U/M: EA; Cap_F: 0.0000000022; Tolerance_%: 10; Value1: Unknown; VDC_V: 25; Value2: 25V; TaMin_C: -55; TaMax_C: 125; SizeArea_mm2: 0.5; SizeAreaWB_mm2: 3; SizeX_mm: 1; SizeZ_mm: 0.6; AEC Category: Q200
C418 = 04025A101FAT2A: CAP, CERM, 100 pF, 50 V, +/- 1%, C0G/NP0, 0402; Manufacturer: AVX; Polarized: N; CompType: Capacitor; Value: 100pF; U/M: EA; Cap_F: 0.0000000001; Tolerance_%: 1; Value1: Unknown; VDC_V: 50; Value2: 50V; TaMin_C: -55; TaMax_C: 125; SizeArea_mm2: 0.5; SizeAreaWB_mm2: 3; SizeZ_mm: 0.6; AEC Category: Q200
J26 J27 OSCinM3 OSCinP3 = 142-0701-201: Connector, TH, SMA; Manufacturer: Emerson Network Power; SymbolCreator: X0208326
J28 = CMP-0077743-1: SMA, 50 Ohm, Gold, TH; Manufacturer: Rosenberger; Gender: Female; Voltage_V: 480V
J75 = 800-10-003-10-001000: Header, 100mil, 3x1, TH; Manufacturer: Mill-Max; SymbolCreator: a0799628
L21 L56 = BLM18SG121TN1D: Ferrite Bead, 120 ohm @ 100 MHz, 3 A, 0603; Manufacturer: MuRata; Value: 120 ohm; Imax_A: 3; DCR_ohm: 0.025; Value1: 0.025 ohm; Value2: 3A; SizeAreaWB_mm2: 4.68; SizeArea_mm2: 1.28; SizeX_mm: 1.6; SizeY_mm: 0.8; SizeZ_mm: 1; ZTyp@100MHz_Ohm: 120
R163 R166 = CRCW04021K50JNED: RES, 1.5 k, 5%, 0.063 W, 0402; Manufacturer: Vishay-Dale; CompType: Resistor; Value: 1.5k; Res_ohm: 1500; Value_Code: 1k50; Tolerance_%: 5; Power_W: 0.063; Value2: 0.063W; VDC_V: 50; TempCo: 200 ppm/C; SizeArea_mm2: 0.5; SizeX_mm: 1; SizeZ_mm: 0.6; EIA_Code: E24; U/M: EA; AEC Category: Q200
R271 R272 R277 R280 R285-R287 R293 R295 R303 R304 R306 R310 R313-R318 R320 R322 R325 R343 R346 R350 R355 R359-R361 = CRCW04020000Z0ED: as R245-R257 on sheet TIDA-01022-E3_LMK00304_Buffer
R273 R274 R276 R279 R282 R283 R288 R289 R292 R294 R299 R300 = CRCW0402120RJNED: RES, 120, 5%, 0.063 W, 0402; Manufacturer: Vishay-Dale; CompType: Resistor; Value: 120; Value_Code: 120R; Tolerance_%: 5; Power_W: 0.063; Value2: 0.063W; VDC_V: 50; TempCo: 200 ppm/C; SizeArea_mm2: 0.5; SizeX_mm: 1; SizeZ_mm: 0.6; EIA_Code: E24; U/M: EA; AEC Category: Q200
R275 = RC0201FR-07620RL: RES, 620, 1%, 0.05 W, 0201; Manufacturer: Yageo America; CompType: Resistor; Value: 620; Value_Code: 620R; Tolerance_%: 1; Power_W: 0.05; Value2: 0.05W; VDC_V: 25; TempCo: 200 ppm/C; SizeArea_mm2: 0.18; SizeX_mm: 0.6; SizeY_mm: 0.3; SizeZ_mm: 0.26; U/M: EA; AEC Category: Q200; AEC Qualified: N
R278 R290 R301 R302 R309 R392 = CRCW02010000Z0ED: RES, 0, 5%, 0.05 W, 0201; Manufacturer: Vishay-Dale; CompType: Resistor; Tolerance_%: 5; Power_W: 0.05; Value: 0; U/M: EA; Value_Code: 0000; Value2: 0.05W; EIA_Code: E24; TempCo: ppm/C; SizeArea_mm2: 0.18; SizeX_mm: 0.6; SizeY_mm: 0.3; SizeZ_mm: 0.26; AEC Category: Q200; AEC Qualified: N
R281 R291 = RC0201JR-0751RL: RES, 51, 5%, 0.05 W, 0201; Manufacturer: Yageo America; CompType: Resistor; Value: 51; Value_Code: 51R0; Tolerance_%: 5; Power_W: 0.05; Value2: 0.05W; VDC_V: 25; TempCo: 200 ppm/C; SizeArea_mm2: 0.18; SizeX_mm: 0.6; SizeY_mm: 0.3; SizeZ_mm: 0.26; EIA_Code: E24; U/M: EA; AEC Category: Q200; AEC Qualified: N
R284 = RC0201FR-0739KL: RES, 39.0 k, 1%, 0.05 W, 0201; Manufacturer: Yageo America; CompType: Resistor; Value: 39.0k; Res_ohm: 39000; Value_Code: 39k0; Tolerance_%: 1; Power_W: 0.05; Value2: 0.05W; VDC_V: 25; TempCo: 200 ppm/C; SizeArea_mm2: 0.18; SizeX_mm: 0.6; SizeY_mm: 0.3; SizeZ_mm: 0.26; U/M: EA; AEC Category: Q200; AEC Qualified: N
R296 = CRCW06030000Z0EA: RES, 0, 5%, 0.1 W, 0603; Manufacturer: Vishay-Dale; CompType: Resistor; Tolerance_%: 5; VDC_V: 75; Power_W: 0.1; Value: 0; U/M: EA; Value_Code: 0000; Value2: 0.1W; EIA_Code: E24; TempCo: 200 ppm/C; SizeArea_mm2: 1.28; SizeX_mm: 1.6; SizeY_mm: 0.8; SizeZ_mm: 1; AEC Category: Q200
R297 R298 R311 R312 = CRCW020149R9FKED: RES, 49.9, 1%, 0.05 W, 0201; Manufacturer: Vishay-Dale; CompType: Resistor; Value: 49.9; Value_Code: 49R9; Tolerance_%: 1; Power_W: 0.05; Value2: 0.05W; VDC_V: 30; TempCo: 100 ppm/C; SizeArea_mm2: 0.18; SizeX_mm: 0.6; SizeY_mm: 0.3; SizeZ_mm: 0.26; EIA_Code: E96; U/M: EA; AEC Category: Q200; AEC Qualified: N
R305 = ERJ-1GEF1000C: RES, 100, 1%, 0.05 W, 0201; Manufacturer: Panasonic; CompType: Resistor; Value: 100; Value_Code: 100R; Tolerance_%: 1; Power_W: 0.05; Value2: 0.05W; VDC_V: 25; TempCo: 200 ppm/C; SizeArea_mm2: 0.18; SizeX_mm: 0.6; SizeY_mm: 0.3; SizeZ_mm: 0.26; EIA_Code: E96; U/M: EA; AEC Category: Q200
R307 R308 = RC0201FR-07294RL: RES, 294, 1%, 0.05 W, 0201; Manufacturer: Yageo America; CompType: Resistor; Value: 294; Value_Code: 294R; Tolerance_%: 1; Power_W: 0.05; Value2: 0.05W; VDC_V: 25; TempCo: 200 ppm/C; SizeArea_mm2: 0.18; SizeX_mm: 0.6; SizeY_mm: 0.3; SizeZ_mm: 0.26; EIA_Code: E96; U/M: EA; AEC Category: Q200; AEC Qualified: N
R319 R341 = CRCW040249R9FKED: RES, 49.9, 1%, 0.063 W, 0402; Manufacturer: Vishay-Dale; CompType: Resistor; Value: 49.9; Value_Code: 49R9; Tolerance_%: 1; Power_W: 0.063; Value2: 0.063W; VDC_V: 50; TempCo: 100 ppm/C; EIA_Code: E96; U/M: EA; AEC Category: Q200
R321 R340 = CRCW0402130RFKED: RES, 130, 1%, 0.063 W, 0402; Manufacturer: Vishay-Dale; CompType: Resistor; Value: 130; Value_Code: 130R; Tolerance_%: 1; Power_W: 0.063; Value2: 0.063W; VDC_V: 50; TempCo: 100 ppm/C; SizeArea_mm2: 0.5; SizeZ_mm: 0.6; EIA_Code: E96; U/M: EA; AEC Category: Q200
R323 R326 R356 R357 = CRCW04020000Z0ED: RES, 0, 5%, 0.063 W, 0402; Manufacturer: Vishay-Dale; CompType: Resistor; Value: 0; Value_Code: 0000; Tolerance_%: 5; Power_W: 0.063; Value2: 0.063W; VDC_V: 50; TempCo: 200 ppm/C; EIA_Code: E24; U/M: EA; AEC Category: Q200
R324 R327 = CRCW040218R0JNED: RES, 18, 5%, 0.063 W, 0402; Manufacturer: Vishay-Dale; CompType: Resistor; Value: 18; Value_Code: 18R0; Tolerance_%: 5; Power_W: 0.063; Value2: 0.063W; VDC_V: 50; TempCo: 200 ppm/C; EIA_Code: E24; U/M: EA; AEC Category: Q200
R328-R339 R362-R365 = CRCW0402240RJNED: RES, 240, 5%, 0.063 W, 0402; Manufacturer: Vishay-Dale; CompType: Resistor; Value: 240; Value_Code: 240R; Tolerance_%: 5; Power_W: 0.063; Value2: 0.063W; VDC_V: 50; TempCo: 200 ppm/C; SizeArea_mm2: 0.5; SizeX_mm: 1; SizeZ_mm: 0.6; EIA_Code: E24; U/M: EA; AEC Category: Q200
R342 R345 R349 R354 = CRCW040220R0FKED: RES, 20.0, 1%, 0.063 W, 0402; Manufacturer: Vishay-Dale; CompType: Resistor; Value: 20.0; Res_ohm: 20; Value_Code: 20R0; Tolerance_%: 1; Power_W: 0.063; Value2: 0.063W; VDC_V: 50; TempCo: 100 ppm/C; SizeArea_mm2: 0.5; SizeZ_mm: 0.6; EIA_Code: E96; U/M: EA; AEC Category: Q200
R344 = CRCW0402100RFKED: RES, 100, 1%, 0.063 W, 0402; Manufacturer: Vishay-Dale; CompType: Resistor; Value: 100; Value_Code: 100R; Tolerance_%: 1; Power_W: 0.063; Value2: 0.063W; VDC_V: 50; TempCo: 100 ppm/C; EIA_Code: E96; U/M: EA; AEC Category: Q200; SizeArea_mm2: 0.5; SizeZ_mm: 0.6
R347 R348 R366 R367 = CRCW0402220RJNED: RES, 220, 5%, 0.063 W, 0402; Manufacturer: Vishay-Dale; CompType: Resistor; Value: 220; Value_Code: 220R; Tolerance_%: 5; Power_W: 0.063; Value2: 0.063W; VDC_V: 50; TempCo: 200 ppm/C; SizeArea_mm2: 0.5; SizeX_mm: 1; SizeZ_mm: 0.6; EIA_Code: E24; U/M: EA; AEC Category: Q200
R351 = RC0603FR-0782RL: RES, 82.0, 1%, 0.1 W, 0603; Manufacturer: Yageo America; CompType: Resistor; Value: 82.0; Res_ohm: 82; Value_Code: 82R0; Tolerance_%: 1; Power_W: 0.1; Value2: 0.1W; VDC_V: 150; TempCo: 200 ppm/C; SizeArea_mm2: 1.28; SizeX_mm: 1.6; SizeY_mm: 0.8; U/M: EA; AEC Category: Q200
R352 R353 R358 = CRCW04021K20JNED: RES, 1.2 k, 5%, 0.063 W, 0402; Manufacturer: Vishay-Dale; CompType: Resistor; Value: 1.2k; Res_ohm: 1200; Value_Code: 1k20; Tolerance_%: 5; Power_W: 0.063; Value2: 0.063W; VDC_V: 50; TempCo: 200 ppm/C; EIA_Code: E24; U/M: EA; AEC Category: Q200; SizeArea_mm2: 0.5; SizeX_mm: 1; SizeZ_mm: 0.6
T3 = TFMR_5_TC1-1-13M+: RF Transformer; Manufacturer: Mini-Circuits
U24 = LMK04828: LMK04828BISQE/NOPB; Manufacturer: Texas Instruments
U25 = LMK61E2-SIAR: Ultra-Low Jitter Programmable Oscillator with Internal EEPROM, SIA0008B; Alternate PartNumber: LMK61E2-SIAT; Manufacturer: Texas Instruments; SymbolCreator: Altium; CompType: IC; U/M: EA
Y1 = CVHD-950-100.000: VCXO, 100 MHz, 3.3V, SMD; Manufacturer: Crystek Corporation; SymbolCreator: a0412235; CompType: Oscillator; U/M: EA; TaMin_C: 0; TaMax_C: 70; Frequency Stability: ±20ppm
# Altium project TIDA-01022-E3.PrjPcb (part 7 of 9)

## Sheet TIDA-01022-E3_FMC+CONN2_1.SchDoc: FMC+CONN2
size 431 x 279 mm; Date: Not shown in title block; ApprovedBy: Not shown in title block; CheckedBy: Not shown in title block; Author: Not shown in title block; CompanyName: Not shown in title block; DrawnBy: Avinash N; Engineer: Not shown in title block; Organization: Not shown in title block; Address1: Not shown in title block; Address2: Not shown in title block; Address3: Not shown in title block; Address4: Not shown in title block; DocumentNumber: 1; Revision: Use project parameter SCH_Rev; SheetNumber: 19; SheetTotal: 26; PageSetup: Record=PageOptions¦CenterHorizontal=True¦CenterVertical=True¦PrintScale=1.00¦XCorrection=1.00¦YCorrection=1.00¦PrintKind=0¦BorderSize=5000000¦LeftOffset=0¦BottomOffset=0¦Orientation=2¦PaperLength=1000¦PaperWidth=1000¦Scale=100¦PaperSource=15¦PrintQuality=600¦MediaType=1¦DitherType=10¦PaperKind=Letter¦PrintScaleMode=1

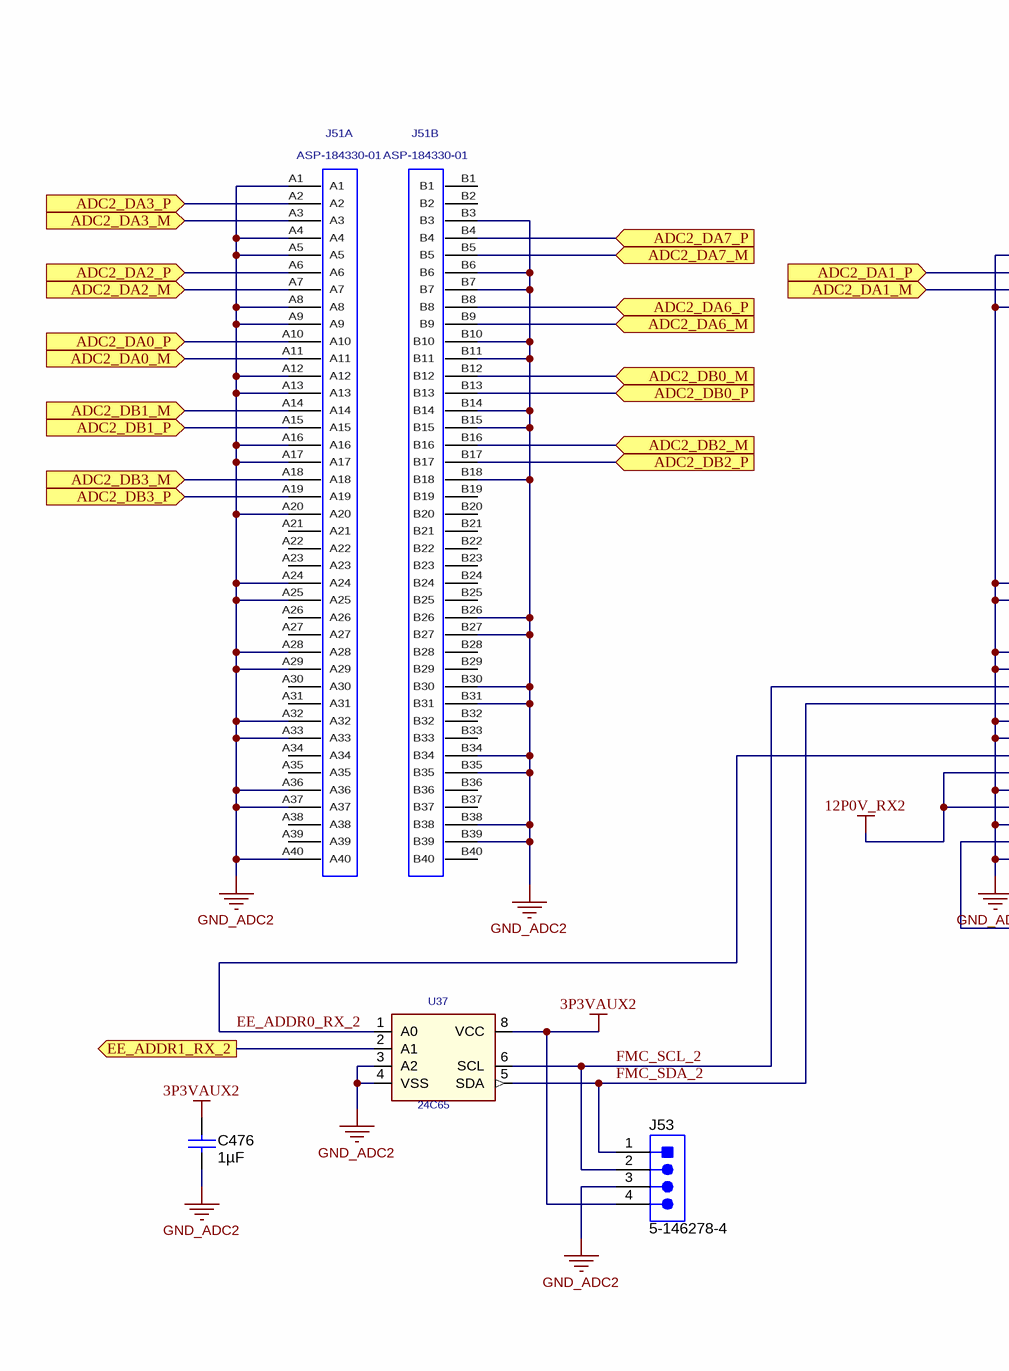
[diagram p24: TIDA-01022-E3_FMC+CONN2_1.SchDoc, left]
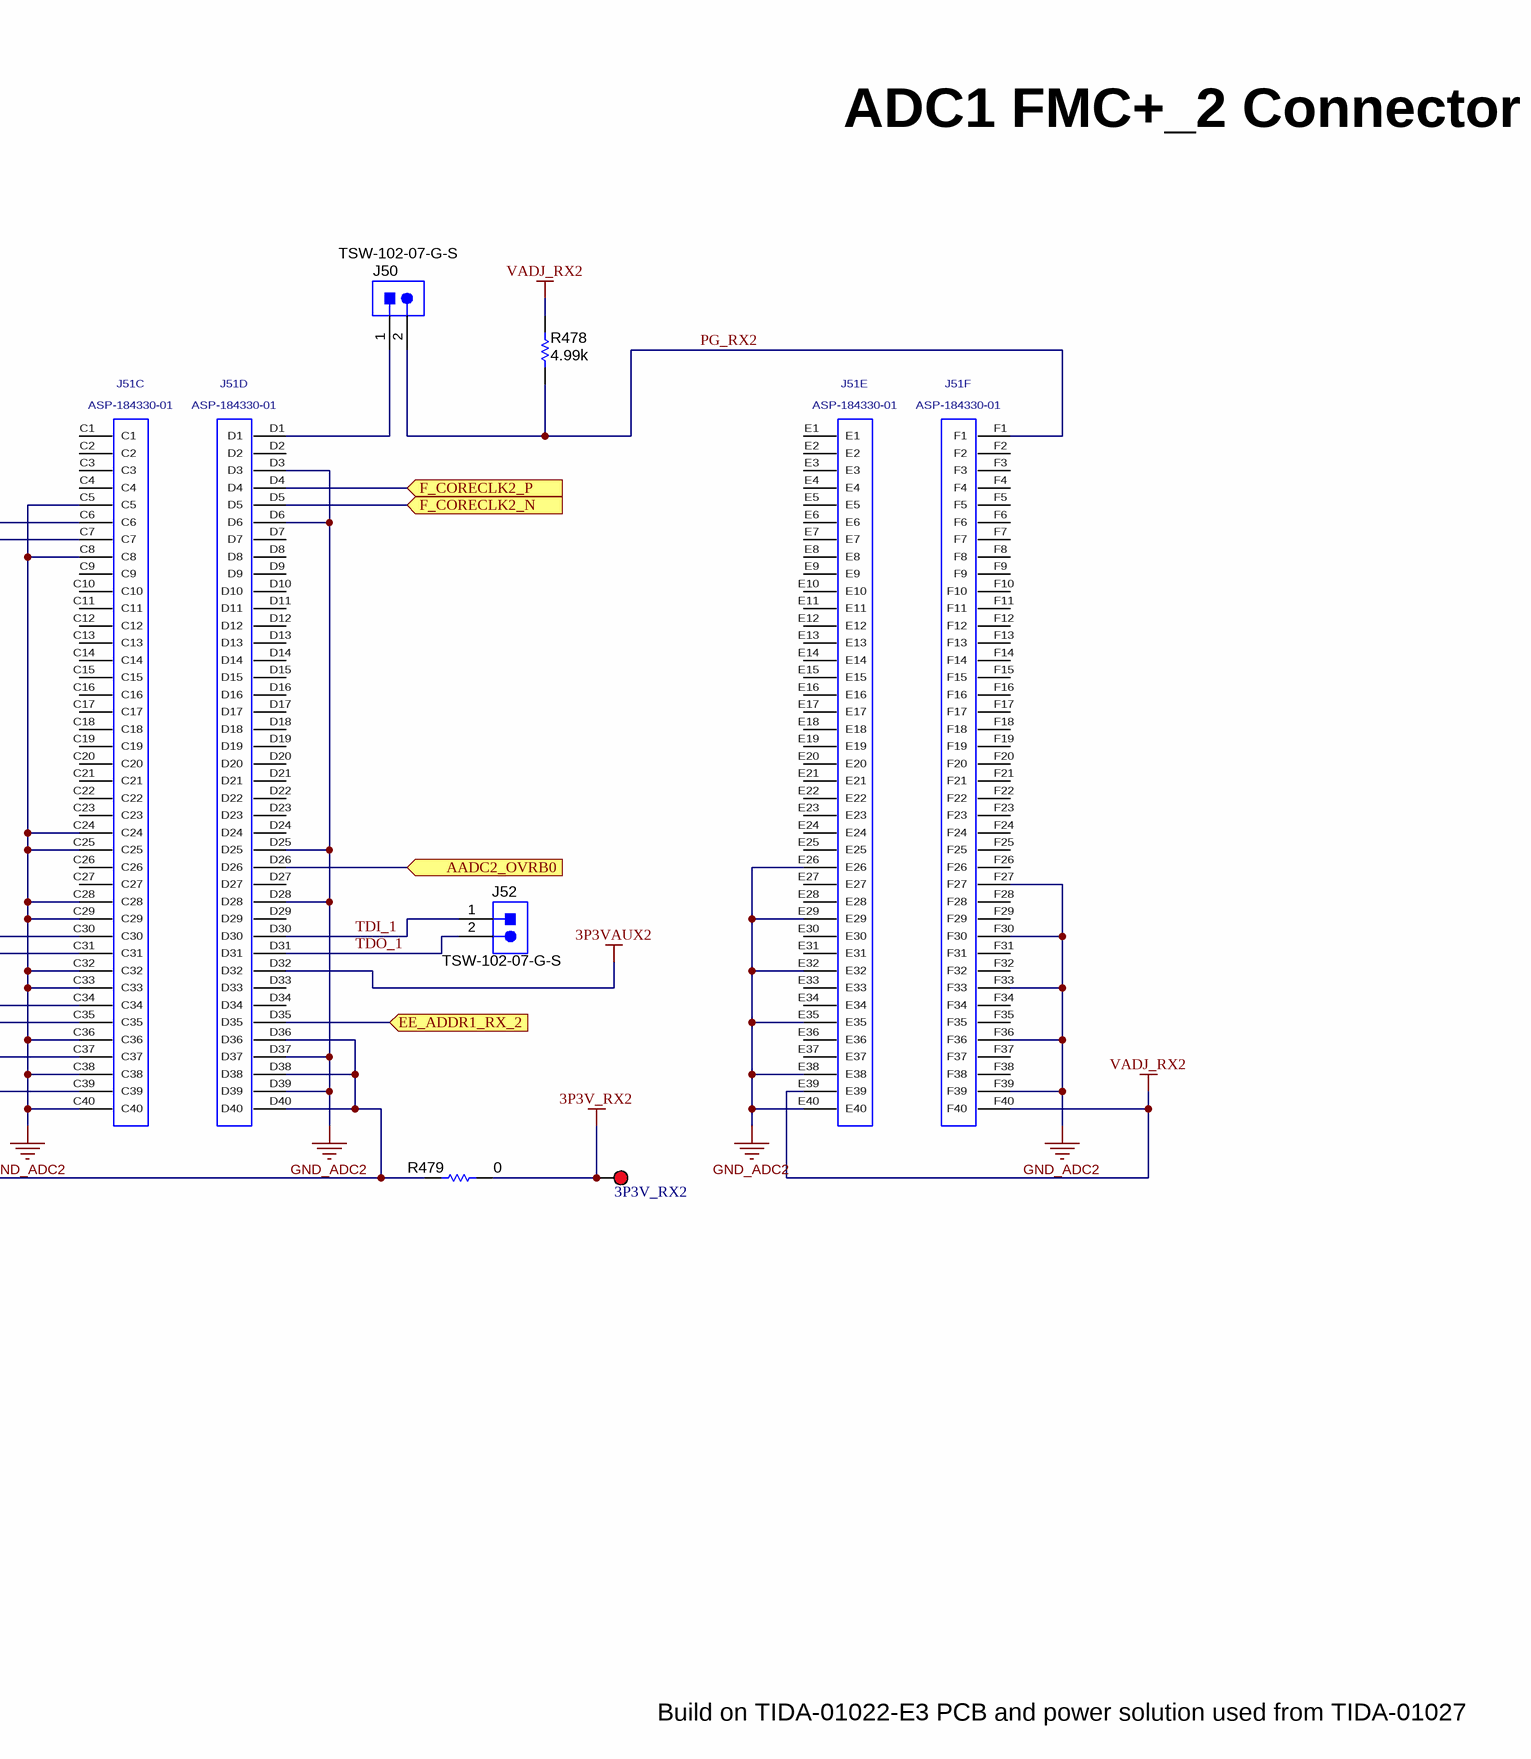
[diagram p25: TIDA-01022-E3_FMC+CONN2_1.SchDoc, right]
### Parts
3P3V_RX2  5000  [Keystone5000]  (value not drawn)
C476  ValueDisplayed: 1µF  [0603]  (hidden comment: C1608X5R1A105K080AC)
J50  TSW-102-07-G-S  [TSW-102-07-G-S]
J51  ASP-184330-01  [ASP-184330-01]  (parts A,B,C,D,E,F of 14)
J52  TSW-102-07-G-S  [TSW-102-07-G-S]
J53  5-146278-4  [TE_5-146278-4]
R478  ValueDisplayed: 4.99k  [0402]  (hidden comment: CRCW04024K99FKED)
R479  ValueDisplayed: 0  [0402]  (hidden comment: CRCW04020000Z0ED)
U37  24C65  [SOIC127P800X216-8N]

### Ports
AADC2_OVRB0 (in), ADC2_DA0_M (in), ADC2_DA0_P (in), ADC2_DA1_M (in), ADC2_DA1_P (in), ADC2_DA2_M (in), ADC2_DA2_P (in), ADC2_DA3_M (in), ADC2_DA3_P (in), ADC2_DA6_M (in), ADC2_DA6_P (in), ADC2_DA7_M (in), ADC2_DA7_P (in), ADC2_DB0_M (in), ADC2_DB0_P (in), ADC2_DB1_M (in), ADC2_DB1_P (in), ADC2_DB2_M (in), ADC2_DB2_P (in), ADC2_DB3_M (in), ADC2_DB3_P (in), EE_ADDR1_RX_2 (in), EE_ADDR1_RX_2 (out), F_CORECLK2_N (in), F_CORECLK2_P (in)

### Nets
3P3V_RX2: 3P3V_RX2.1 R479.1
3P3VAUX2: C476.1 J51.D32 J53.4 U37.8(VCC)
12P0V_RX2: J51.C35 J51.C37
GND_ADC2: C476.2 J51.A1 J51.A4 J51.A5 J51.A8 J51.A9 J51.A12 J51.A13 J51.A16 J51.A17 J51.A20 J51.A24 J51.A25 J51.A28 J51.A29 J51.A32 J51.A33 J51.A36 J51.A37 J51.A40 J51.B3 J51.B6 J51.B7 J51.B10 J51.B11 J51.B14 J51.B15 J51.B18 J51.B26 J51.B27 J51.B30 J51.B31 J51.B34 J51.B35 J51.B38 J51.B39 J51.C5 J51.C8 J51.C24 J51.C25 J51.C28 J51.C29 J51.C32 J51.C33 J51.C36 J51.C38 J51.C40 J51.D3 J51.D6 J51.D25 J51.D28 J51.D37 J51.D39 J51.E26 J51.E29 J51.E32 J51.E35 J51.E38 J51.E40 J51.F27 J51.F30 J51.F33 J51.F36 J51.F39 J53.3 U37.3(A2) U37.4(VSS)  [project net DGND]
VADJ_RX2: J51.E39 J51.F40 R478.2
AADC2_OVRB0: J51.D26 ; port AADC2_OVRB0
ADC2_DA0_M: J51.A11 ; port ADC2_DA0_M
ADC2_DA0_P: J51.A10 ; port ADC2_DA0_P
ADC2_DA1_M: J51.C7 ; port ADC2_DA1_M
ADC2_DA1_P: J51.C6 ; port ADC2_DA1_P
ADC2_DA2_M: J51.A7 ; port ADC2_DA2_M
ADC2_DA2_P: J51.A6 ; port ADC2_DA2_P
ADC2_DA3_M: J51.A3 ; port ADC2_DA3_M
ADC2_DA3_P: J51.A2 ; port ADC2_DA3_P
ADC2_DA6_M: J51.B9 ; port ADC2_DA6_M
ADC2_DA6_P: J51.B8 ; port ADC2_DA6_P
ADC2_DA7_M: J51.B5 ; port ADC2_DA7_M
ADC2_DA7_P: J51.B4 ; port ADC2_DA7_P
ADC2_DB0_M: J51.B12 ; port ADC2_DB0_M
ADC2_DB0_P: J51.B13 ; port ADC2_DB0_P
ADC2_DB1_M: J51.A14 ; port ADC2_DB1_M
ADC2_DB1_P: J51.A15 ; port ADC2_DB1_P
ADC2_DB2_M: J51.B16 ; port ADC2_DB2_M
ADC2_DB2_P: J51.B17 ; port ADC2_DB2_P
ADC2_DB3_M: J51.A18 ; port ADC2_DB3_M
ADC2_DB3_P: J51.A19 ; port ADC2_DB3_P
EE_ADDR0_RX_2: J51.C34 U37.1(A0)
EE_ADDR1_RX_2: J51.D35 U37.2(A1) ; port EE_ADDR1_RX_2
F_CORECLK2_N: J51.D5 ; port F_CORECLK2_N
F_CORECLK2_P: J51.D4 ; port F_CORECLK2_P
FMC_SCL_2: J51.C30 J53.2 U37.6(SCL)
FMC_SDA_2: J51.C31 J53.1 U37.5(SDA)
PG_RX2: J50.2 J51.F1 R478.1
TDI_1: J51.D30 J52.1
TDO_1: J51.D31 J52.2
NetJ50_1: J50.1 J51.D1
NetJ51_C39: J51.C39 J51.D36 J51.D38 J51.D40 R479.2

Not connected (* = marked no-connect by the designer): J51 A21 A22 A23 A26 A27 A30 A31 A34 A35 A38 A39 B1 B2 B19 B20 B21 B22 B23 B24 B25 B28 B29 B32 B33 B36 B37 B40 C1 C2 C3 C4 C9 C10 C11 C12 C13 C14 C15 C16 C17 C18 C19 C20 C21 C22 C23 C26 C27 D2 D7 D8 D9 D10 D11 D12 D13 D14 D15 D16 D17 D18 D19 D20 D21 D22 D23 D24 D27 D29 D33 D34 E1 E2 E3 E4 E5 E6 E7 E8 E9 E10 E11 E12 E13 E14 E15 E16 E17 E18 E19 E20 E21 E22 E23 E24 E25 E27 E28 E30 E31 E33 E34 E36 E37 F2 F3 F4 F5 F6 F7 F8 F9 F10 F11 F12 F13 F14 F15 F16 F17 F18 F19 F20 F21 F22 F23 F24 F25 F26 F28 F29 F31 F32 F34 F35 F37 F38

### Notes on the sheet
- ADC1 FMC+_2 Connector
- Build on TIDA-01022-E3 PCB and power solution used from TIDA-01027

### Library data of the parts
3P3V_RX2 = 5000: Test Point, Miniature, Red, TH; Manufacturer: Keystone; CompType: Test Point Loop; ContactFinish: Silver; Green_Lifecycle: Active; Green_REACh: Passed
C476 = C1608X5R1A105K080AC: CAP, CERM, 1 µF, 10 V, +/- 10%, X5R, 0603; Manufacturer: TDK; Polarized: N; CompType: Capacitor; Value: 1uF; U/M: EA; Cap_F: 0.000001; Tolerance_%: 10; Value1: Unknown; Value2: 10V; TaMin_C: -55; TaMax_C: 85; SizeArea_mm2: 1.28; SizeAreaWB_mm2: 4.68; SizeX_mm: 1.6; SizeY_mm: 0.8; SizeZ_mm: 1; AEC Category: Q200
J50 J52 = TSW-102-07-G-S: Header, 100mil, 2x1, Gold, TH; Manufacturer: Samtec; SymbolCreator: a0412235; Pitch_mm: 2.54; Gender: Male; Shrouded: N; Row_Count: 1; Current_A: 6.3; Voltage_V: 550; Cert_CSA: Y
J51 = ASP-184330-01: 14 ROW .050 PITCH TERMINAL ARRAY ASM.; Manufacturer: SAMTEC
J53 = 5-146278-4: Header, 100mil, 4x1, Tin, TH; Manufacturer: TE Connectivity; SymbolCreator: a0412235
R478 = CRCW04024K99FKED: RES, 4.99 k, 1%, 0.063 W, 0402; Manufacturer: Vishay-Dale; CompType: Resistor; Value: 4.99k; Res_ohm: 4990; Value_Code: 4k99; Tolerance_%: 1; Power_W: 0.063; Value2: 0.063W; VDC_V: 50; TempCo: 100 ppm/C; SizeArea_mm2: 0.5; SizeZ_mm: 0.6; EIA_Code: E96; U/M: EA; AEC Category: Q200
R479 = CRCW04020000Z0ED: RES, 0, 5%, 0.063 W, 0402; Manufacturer: Vishay-Dale; CompType: Resistor; Value: 0; Value_Code: 0000; Tolerance_%: 5; Power_W: 0.063; Value2: 0.063W; VDC_V: 50; TempCo: 200 ppm/C; SizeArea_mm2: 0.5; SizeX_mm: 1; SizeZ_mm: 0.6; EIA_Code: E24; U/M: EA; AEC Category: Q200
U37 = 24LC65: 64K I2C Smart Serial EEPROM, SOIC-8; PartNumber: 24C65T-I/SM; Manufacturer: MICROCHIP TECHNOLOGY_DNI; NC: 7

## Sheet TIDA-01022-E3_FMC+CONN2_2.SchDoc: FMC+CONN2
size 431 x 279 mm; Date: Not shown in title block; ApprovedBy: Not shown in title block; CheckedBy: Not shown in title block; Author: Not shown in title block; CompanyName: Not shown in title block; DrawnBy: Avinash N; Engineer: Not shown in title block; Organization: Not shown in title block; Address1: Not shown in title block; Address2: Not shown in title block; Address3: Not shown in title block; Address4: Not shown in title block; DocumentNumber: 1; Revision: Use project parameter SCH_Rev; SheetNumber: 20; SheetTotal: 26; PageSetup: Record=PageOptions¦CenterHorizontal=True¦CenterVertical=True¦PrintScale=1.00¦XCorrection=1.00¦YCorrection=1.00¦PrintKind=0¦BorderSize=5000000¦LeftOffset=0¦BottomOffset=0¦Orientation=2¦PaperLength=1000¦PaperWidth=1000¦Scale=100¦PaperSource=15¦PrintQuality=600¦MediaType=1¦DitherType=10¦PaperKind=Letter¦PrintScaleMode=1

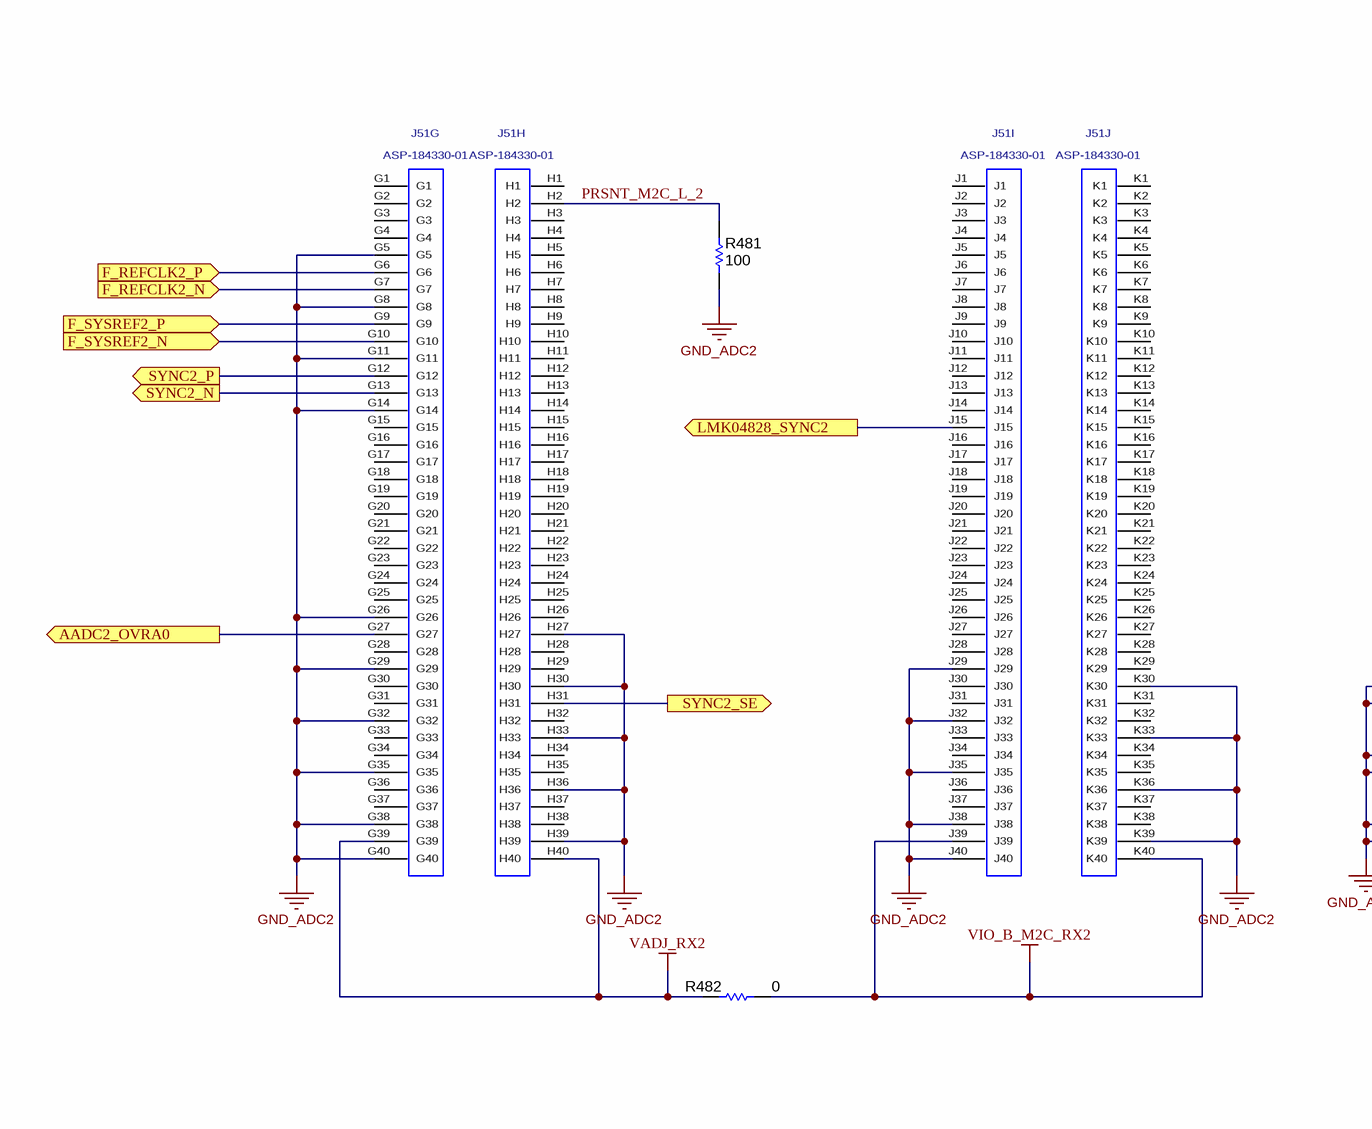
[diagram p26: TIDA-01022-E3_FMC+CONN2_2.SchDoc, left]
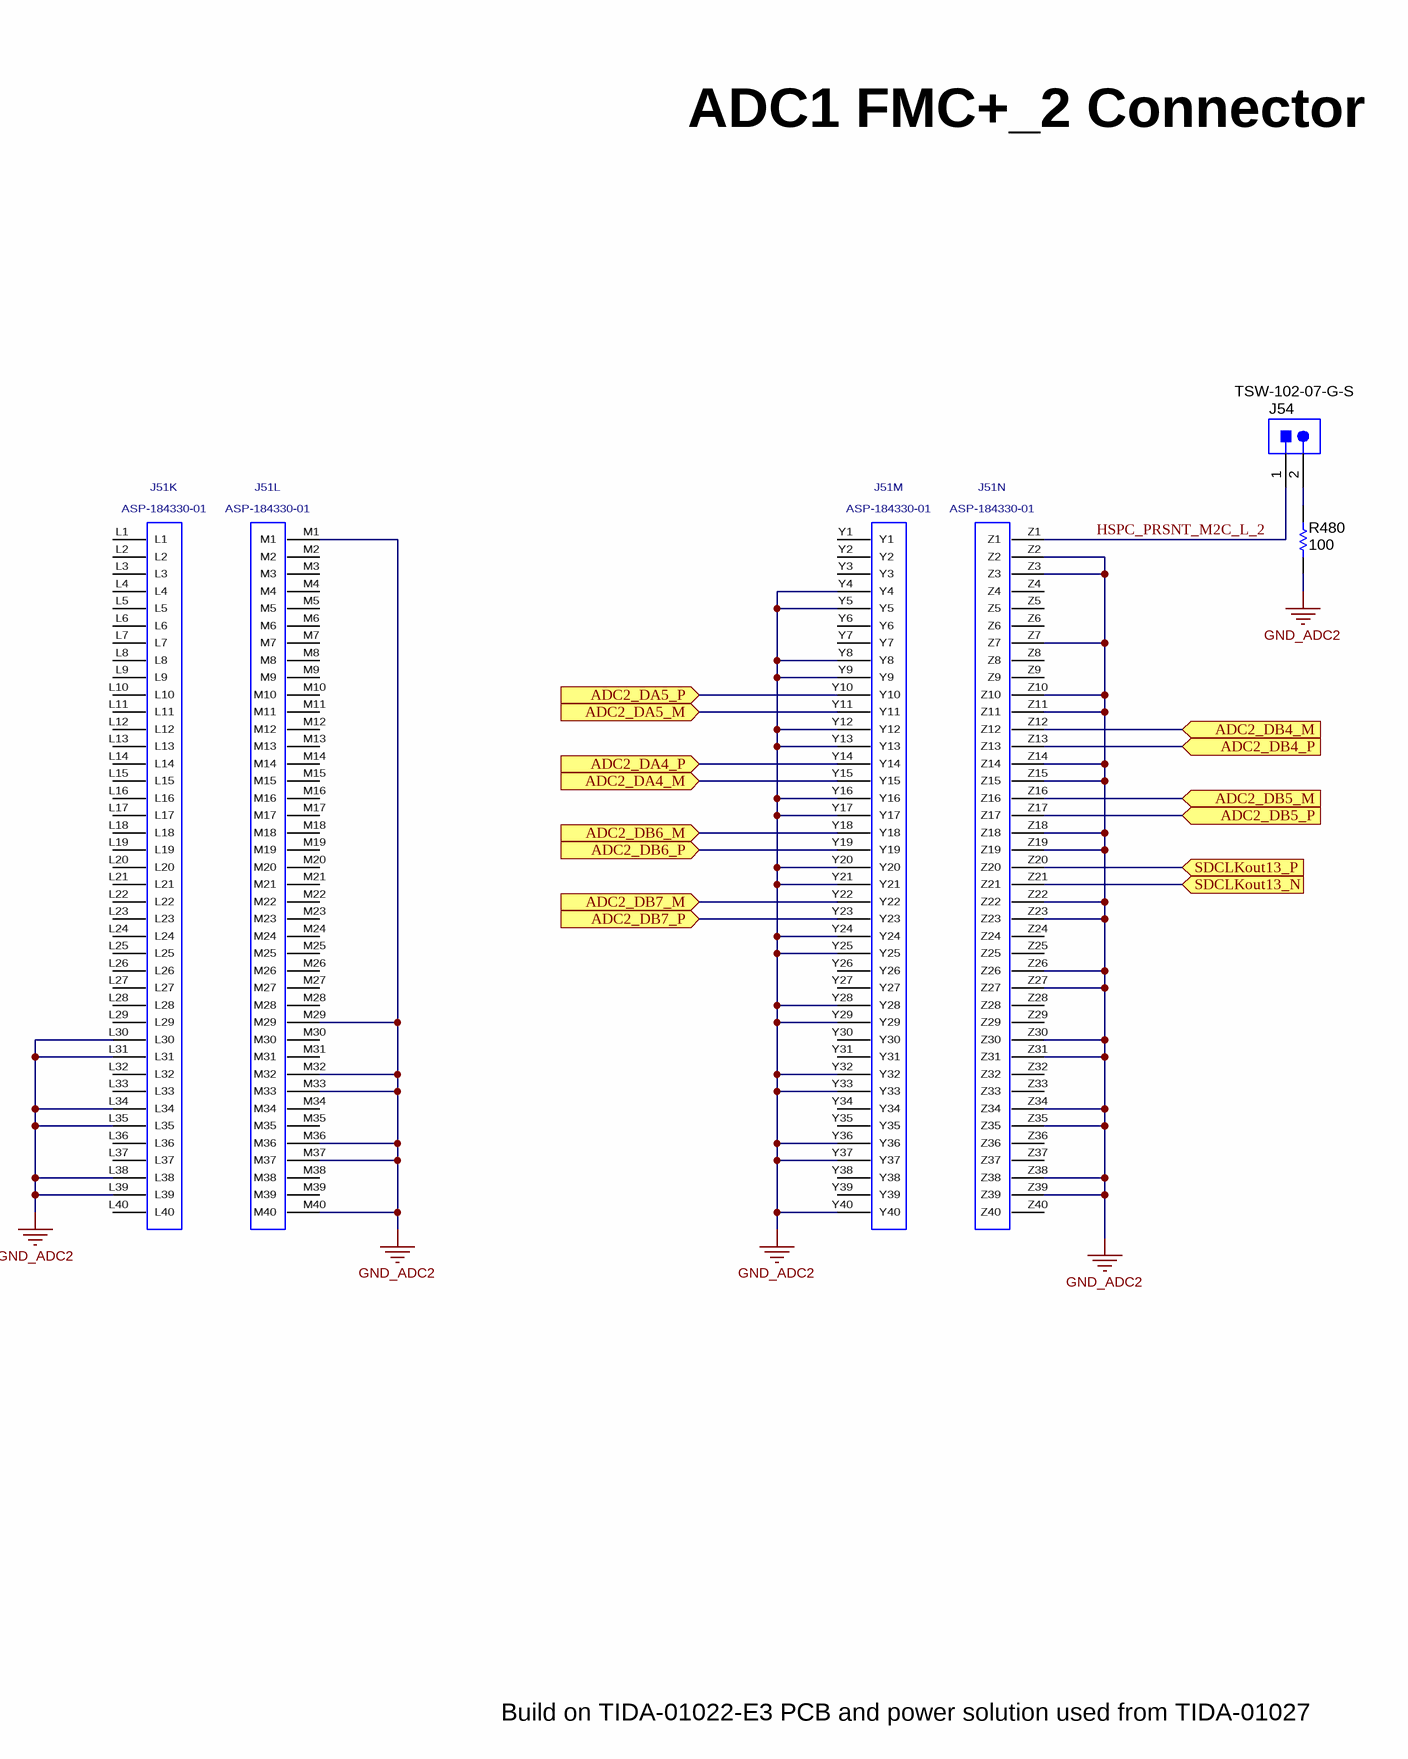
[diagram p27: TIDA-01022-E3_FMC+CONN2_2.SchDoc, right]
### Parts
J51  ASP-184330-01  [ASP-184330-01]  (parts G,H,I,J,K,L,M,N of 14)
J54  TSW-102-07-G-S  [TSW-102-07-G-S]
R480  ValueDisplayed: 100  [0402]  (hidden comment: CRCW0402100RJNED)
R481  ValueDisplayed: 100  [0402]  (hidden comment: CRCW0402100RJNED)
R482  ValueDisplayed: 0  [0402]  (hidden comment: CRCW04020000Z0ED)

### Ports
AADC2_OVRA0 (out), ADC2_DA4_M (in), ADC2_DA4_P (in), ADC2_DA5_M (in), ADC2_DA5_P (in), ADC2_DB4_M (in), ADC2_DB4_P (in), ADC2_DB5_M (in), ADC2_DB5_P (in), ADC2_DB6_M (in), ADC2_DB6_P (in), ADC2_DB7_M (in), ADC2_DB7_P (in), F_REFCLK2_N (in), F_REFCLK2_P (in), F_SYSREF2_N (in), F_SYSREF2_P (in), LMK04828_SYNC2 (out), SDCLKout13_N (in), SDCLKout13_P (in), SYNC2_N (out), SYNC2_P (out), SYNC2_SE (out)

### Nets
GND_ADC2: J51.G5 J51.G8 J51.G11 J51.G14 J51.G26 J51.G29 J51.G32 J51.G35 J51.G38 J51.G40 J51.H27 J51.H30 J51.H33 J51.H36 J51.H39 J51.J29 J51.J32 J51.J35 J51.J38 J51.J40 J51.K30 J51.K33 J51.K36 J51.K39 J51.L30 J51.L31 J51.L34 J51.L35 J51.L38 J51.L39 J51.M1 J51.M29 J51.M32 J51.M33 J51.M36 J51.M37 J51.M40 J51.Y4 J51.Y5 J51.Y8 J51.Y9 J51.Y12 J51.Y13 J51.Y16 J51.Y17 J51.Y20 J51.Y21 J51.Y24 J51.Y25 J51.Y28 J51.Y29 J51.Y32 J51.Y33 J51.Y36 J51.Y37 J51.Y40 J51.Z2 J51.Z3 J51.Z7 J51.Z10 J51.Z11 J51.Z14 J51.Z15 J51.Z18 J51.Z19 J51.Z22 J51.Z23 J51.Z26 J51.Z27 J51.Z30 J51.Z31 J51.Z34 J51.Z35 J51.Z38 J51.Z39 R480.1 R481.1  [project net DGND]
VADJ_RX2: J51.G39 J51.H40 R482.2
VIO_B_M2C_RX2: J51.J39 J51.K40 R482.1
AADC2_OVRA0: J51.G27 ; port AADC2_OVRA0
ADC2_DA4_M: J51.Y15 ; port ADC2_DA4_M
ADC2_DA4_P: J51.Y14 ; port ADC2_DA4_P
ADC2_DA5_M: J51.Y11 ; port ADC2_DA5_M
ADC2_DA5_P: J51.Y10 ; port ADC2_DA5_P
ADC2_DB4_M: J51.Z12 ; port ADC2_DB4_M
ADC2_DB4_P: J51.Z13 ; port ADC2_DB4_P
ADC2_DB5_M: J51.Z16 ; port ADC2_DB5_M
ADC2_DB5_P: J51.Z17 ; port ADC2_DB5_P
ADC2_DB6_M: J51.Y18 ; port ADC2_DB6_M
ADC2_DB6_P: J51.Y19 ; port ADC2_DB6_P
ADC2_DB7_M: J51.Y22 ; port ADC2_DB7_M
ADC2_DB7_P: J51.Y23 ; port ADC2_DB7_P
F_REFCLK2_N: J51.G7 ; port F_REFCLK2_N
F_REFCLK2_P: J51.G6 ; port F_REFCLK2_P
F_SYSREF2_N: J51.G10 ; port F_SYSREF2_N
F_SYSREF2_P: J51.G9 ; port F_SYSREF2_P
HSPC_PRSNT_M2C_L_2: J51.Z1 J54.1
LMK04828_SYNC2: J51.J15 ; port LMK04828_SYNC2
PRSNT_M2C_L_2: J51.H2 R481.2
SDCLKout13_N: J51.Z21 ; port SDCLKout13_N
SDCLKout13_P: J51.Z20 ; port SDCLKout13_P
SYNC2_N: J51.G13 ; port SYNC2_N
SYNC2_P: J51.G12 ; port SYNC2_P
SYNC2_SE: J51.H31 ; port SYNC2_SE
NetJ54_2: J54.2 R480.2

Not connected (* = marked no-connect by the designer): J51 G1 G2 G3 G4 G15 G16 G17 G18 G19 G20 G21 G22 G23 G24 G25 G28 G30 G31 G33 G34 G36 G37 H1 H3 H4 H5 H6 H7 H8 H9 H10 H11 H12 H13 H14 H15 H16 H17 H18 H19 H20 H21 H22 H23 H24 H25 H26 H28 H29 H32 H34 H35 H37 H38 J1 J2 J3 J4 J5 J6 J7 J8 J9 J10 J11 J12 J13 J14 J16 J17 J18 J19 J20 J21 J22 J23 J24 J25 J26 J27 J28 J30 J31 J33 J34 J36 J37 K1 K2 K3 K4 K5 K6 K7 K8 K9 K10 K11 K12 K13 K14 K15 K16 K17 K18 K19 K20 K21 K22 K23 K24 K25 K26 K27 K28 K29 K31 K32 K34 K35 K37 K38 L1 L2 L3 L4 L5 L6 L7 L8 L9 L10 L11 L12 L13 L14 L15 L16 L17 L18 L19 L20 L21 L22 L23 L24 L25 L26 L27 L28 L29 L32 L33 L36 L37 L40 M2 M3 M4 M5 M6 M7 M8 M9 M10 M11 M12 M13 M14 M15 M16 M17 M18 M19 M20 M21 M22 M23 M24 M25 M26 M27 M28 M30 M31 M34 M35 M38 M39 Y1 Y2 Y3 Y6 Y7 Y26 Y27 Y30 Y31 Y34 Y35 Y38 Y39 Z4 Z5 Z6 Z8 Z9 Z24 Z25 Z28 Z29 Z32 Z33 Z36 Z37 Z40

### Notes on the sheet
- ADC1 FMC+_2 Connector
- Build on TIDA-01022-E3 PCB and power solution used from TIDA-01027

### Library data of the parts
J51 = ASP-184330-01: as J51 on sheet TIDA-01022-E3_FMC+CONN2_1
J54 = TSW-102-07-G-S: as J50 on sheet TIDA-01022-E3_FMC+CONN2_1
R480 R481 = CRCW0402100RJNED: RES, 100, 5%, 0.063 W, 0402; Manufacturer: Vishay-Dale; CompType: Resistor; Value: 100; Value_Code: 100R; Tolerance_%: 5; Power_W: 0.063; Value2: 0.063W; VDC_V: 50; TempCo: 200 ppm/C; SizeArea_mm2: 0.5; SizeX_mm: 1; SizeZ_mm: 0.6; EIA_Code: E24; U/M: EA; AEC Category: Q200
R482 = CRCW04020000Z0ED: as R479 on sheet TIDA-01022-E3_FMC+CONN2_1

## Sheet TIDA-01022-E3_Power1.SchDoc: Power Supplies
size 431 x 279 mm; Date: Not shown in title block; ApprovedBy: Not shown in title block; CheckedBy: Not shown in title block; Author: Not shown in title block; CompanyName: Not shown in title block; DrawnBy: Avinash N; Engineer: Not shown in title block; Organization: Not shown in title block; Address1: Not shown in title block; Address2: Not shown in title block; Address3: Not shown in title block; Address4: Not shown in title block; DocumentNumber: 1; Revision: Use project parameter SCH_Rev; SheetNumber: 21; SheetTotal: 26; PageSetup: Record=PageOptions¦CenterHorizontal=True¦CenterVertical=True¦PrintScale=1.00¦XCorrection=1.00¦YCorrection=1.00¦PrintKind=0¦BorderSize=5000000¦LeftOffset=0¦BottomOffset=0¦Orientation=2¦PaperLength=1000¦PaperWidth=1000¦Scale=100¦PaperSource=15¦PrintQuality=600¦MediaType=1¦DitherType=10¦PaperKind=Letter¦PrintScaleMode=1

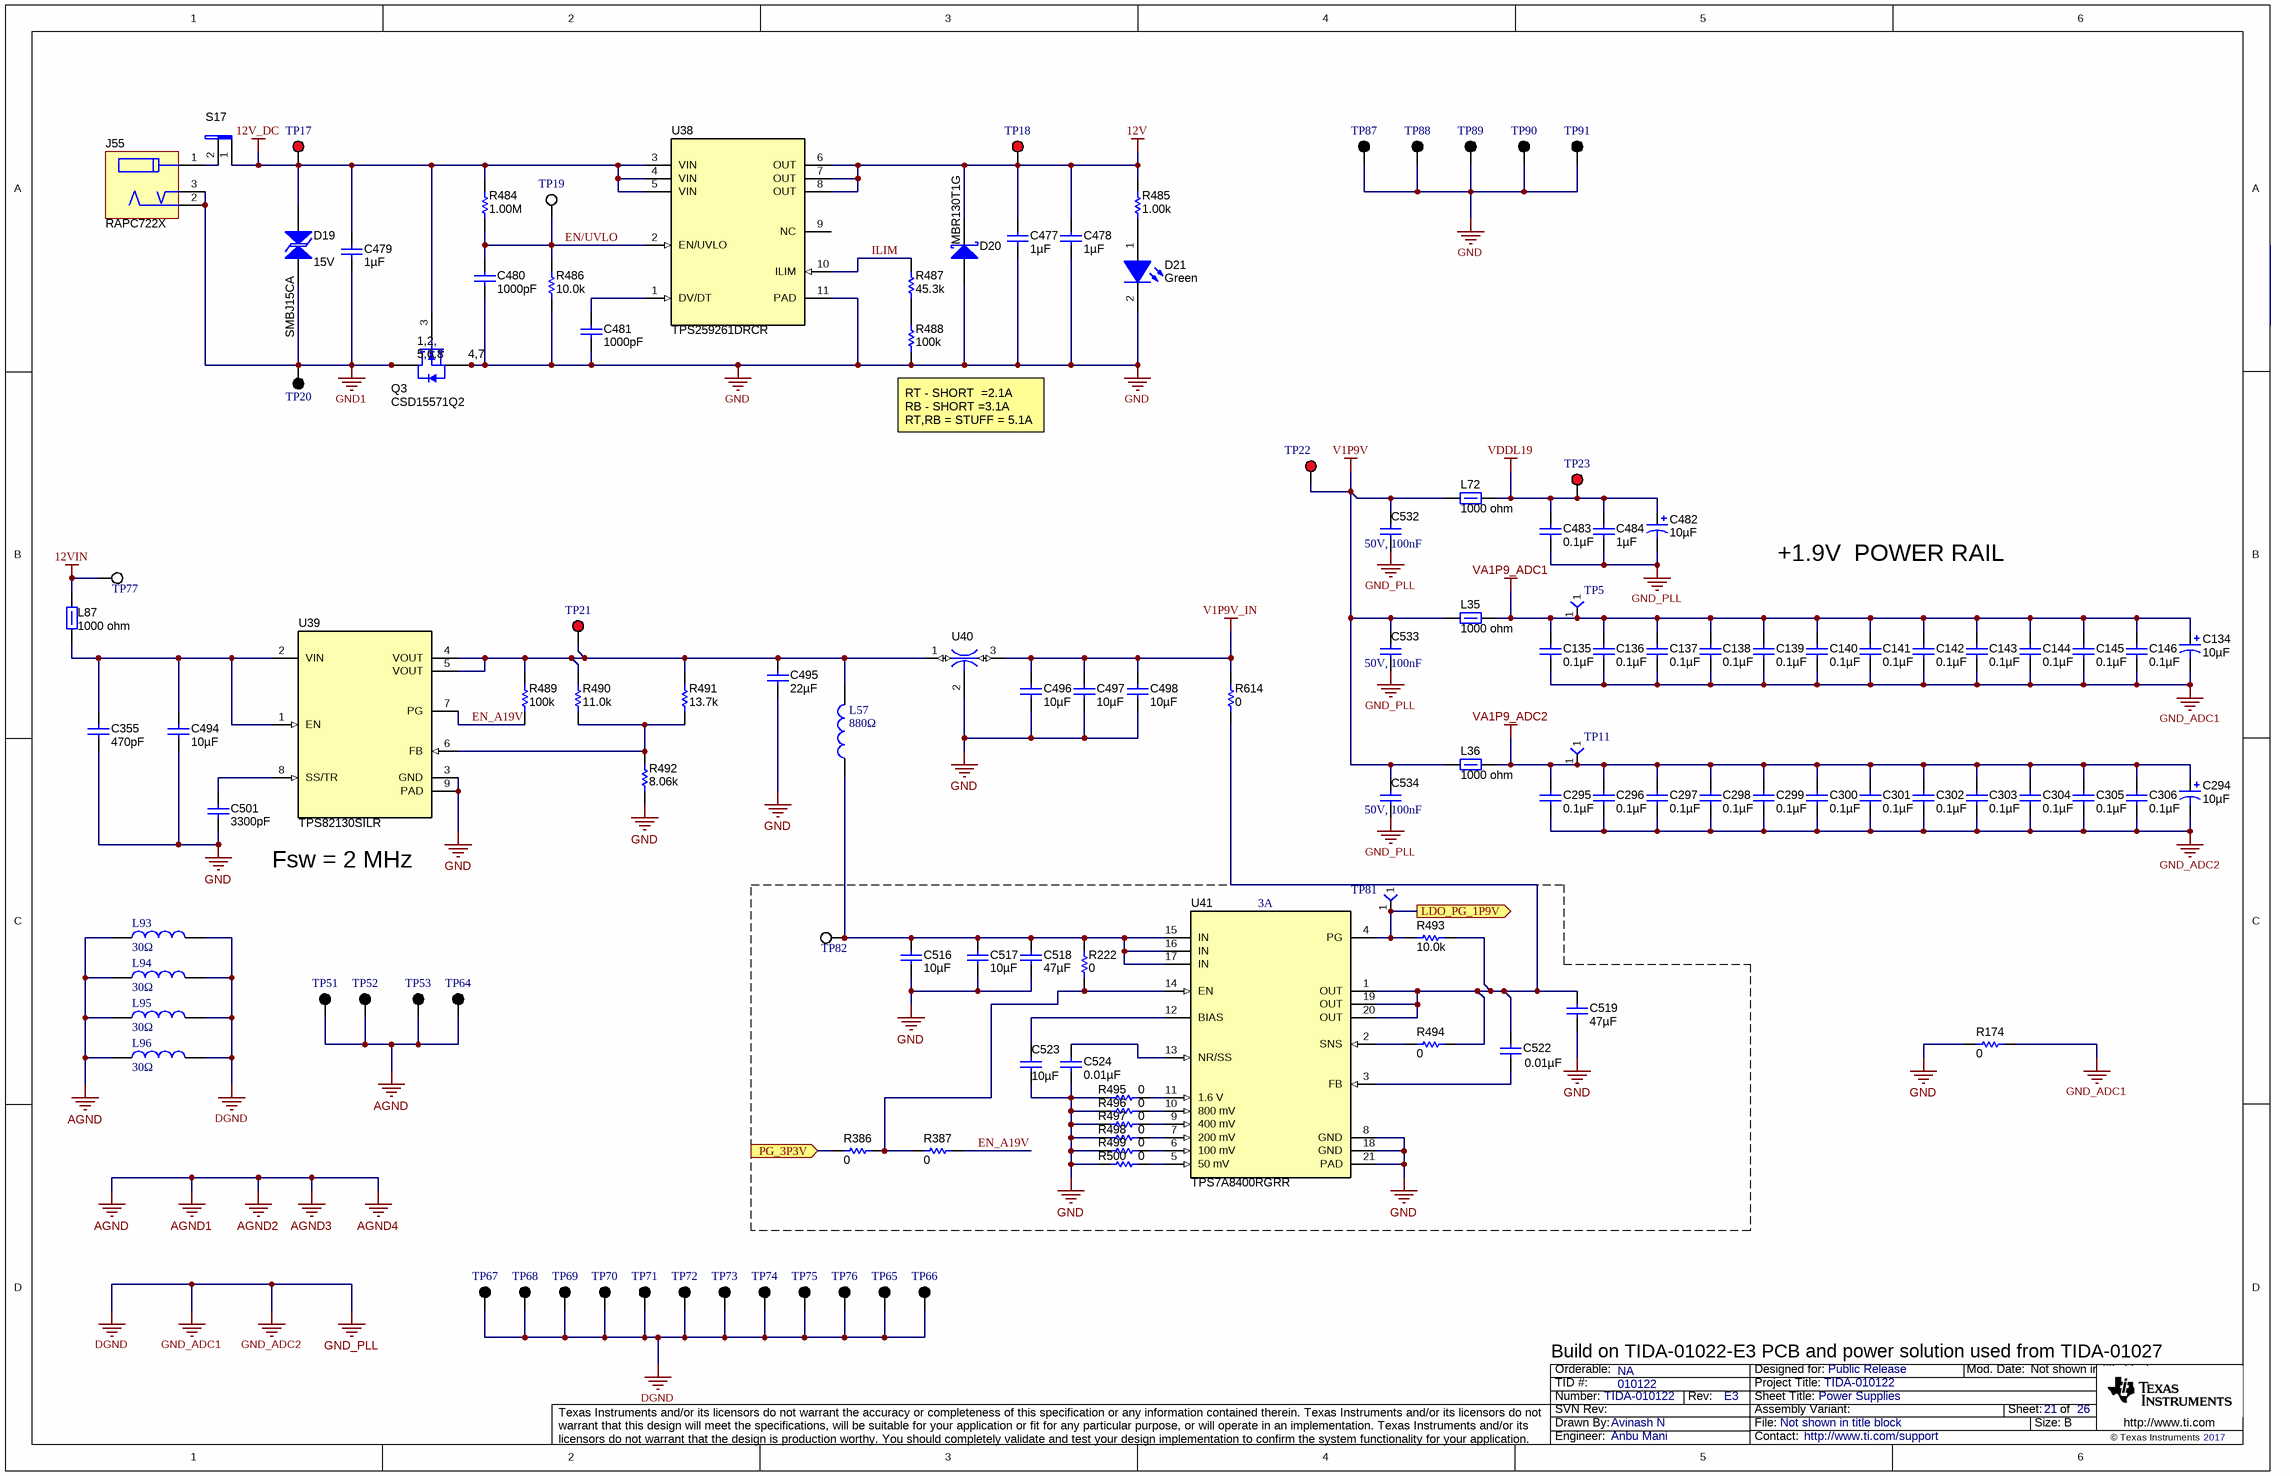
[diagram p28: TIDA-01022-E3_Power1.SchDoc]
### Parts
C134  ValueDisplayed: 10µF  [3528-21]  (hidden comment: 293D106X0010B2TE3)
C135  ValueDisplayed: 0.1µF  [0201]  (hidden comment: GRM033C71A104KE14D)
C136  ValueDisplayed: 0.1µF  [0201]  (hidden comment: GRM033C71A104KE14D)
C137  ValueDisplayed: 0.1µF  [0201]  (hidden comment: GRM033C71A104KE14D)
C138  ValueDisplayed: 0.1µF  [0201]  (hidden comment: GRM033C71A104KE14D)
C139  ValueDisplayed: 0.1µF  [0201]  (hidden comment: GRM033C71A104KE14D)
C140  ValueDisplayed: 0.1µF  [0201]  (hidden comment: GRM033C71A104KE14D)
C141  ValueDisplayed: 0.1µF  [0201]  (hidden comment: GRM033C71A104KE14D)
C142  ValueDisplayed: 0.1µF  [0201]  (hidden comment: GRM033C71A104KE14D)
C143  ValueDisplayed: 0.1µF  [0201]  (hidden comment: GRM033C71A104KE14D)
C144  ValueDisplayed: 0.1µF  [0201]  (hidden comment: GRM033C71A104KE14D)
C145  ValueDisplayed: 0.1µF  [0201]  (hidden comment: GRM033C71A104KE14D)
C146  ValueDisplayed: 0.1µF  [0201]  (hidden comment: GRM033C71A104KE14D)
C294  ValueDisplayed: 10µF  [3528-21]  (hidden comment: 293D106X0010B2TE3)
C295  ValueDisplayed: 0.1µF  [0201]  (hidden comment: GRM033C71A104KE14D)
C296  ValueDisplayed: 0.1µF  [0201]  (hidden comment: GRM033C71A104KE14D)
C297  ValueDisplayed: 0.1µF  [0201]  (hidden comment: GRM033C71A104KE14D)
C298  ValueDisplayed: 0.1µF  [0201]  (hidden comment: GRM033C71A104KE14D)
C299  ValueDisplayed: 0.1µF  [0201]  (hidden comment: GRM033C71A104KE14D)
C300  ValueDisplayed: 0.1µF  [0201]  (hidden comment: GRM033C71A104KE14D)
C301  ValueDisplayed: 0.1µF  [0201]  (hidden comment: GRM033C71A104KE14D)
C302  ValueDisplayed: 0.1µF  [0201]  (hidden comment: GRM033C71A104KE14D)
C303  ValueDisplayed: 0.1µF  [0201]  (hidden comment: GRM033C71A104KE14D)
C304  ValueDisplayed: 0.1µF  [0201]  (hidden comment: GRM033C71A104KE14D)
C305  ValueDisplayed: 0.1µF  [0201]  (hidden comment: GRM033C71A104KE14D)
C306  ValueDisplayed: 0.1µF  [0201]  (hidden comment: GRM033C71A104KE14D)
C355  ValueDisplayed: 470pF  [0402]  (hidden comment: GRM1555C1H471JA01D)
C477  ValueDisplayed: 1µF  [0805_HV]  (hidden comment: 08053D105KAT2A)
C478  ValueDisplayed: 1µF  [0805_HV]  (hidden comment: 08053D105KAT2A)
C479  ValueDisplayed: 1µF  [0805_HV]  (hidden comment: 08053D105KAT2A)
C480  ValueDisplayed: 1000pF  [0603]  (hidden comment: 06031C102MAT2A)
C481  ValueDisplayed: 1000pF  [0603]  (hidden comment: 06031C102MAT2A)
C482  ValueDisplayed: 10µF  [3528-21]  (hidden comment: 293D106X0010B2TE3)
C483  ValueDisplayed: 0.1µF  [0201]  (hidden comment: GRM033C71A104KE14D)
C484  ValueDisplayed: 1µF  [0603]  (hidden comment: C1608X5R1A105K080AC)
C494  ValueDisplayed: 10µF  [1206_190]  (hidden comment: C3216X7R1E106M160AE)
C495  ValueDisplayed: 22µF  [0805_HV]  (hidden comment: JMK212BJ226MG-T)
C496  ValueDisplayed: 10µF  [1206_190]  (hidden comment: C3216X7R1E106M160AE)
C497  ValueDisplayed: 10µF  [1206_190]  (hidden comment: C3216X7R1E106M160AE)
C498  ValueDisplayed: 10µF  [1206_190]  (hidden comment: C3216X7R1E106M160AE)
C501  ValueDisplayed: 3300pF  [0603]  (hidden comment: GRM1885C1H332JA01D)
C516  ValueDisplayed: 10µF  [0805_HV]  (hidden comment: GRM21BR61C106KE15L)
C517  ValueDisplayed: 10µF  [0805_HV]  (hidden comment: GRM21BR61C106KE15L)
C518  ValueDisplayed: 47µF  [0805_HV]  (hidden comment: GRM219R60G476ME44D)
C519  ValueDisplayed: 47µF  [0805_HV]  (hidden comment: GRM219R60G476ME44D)
C522  ValueDisplayed: 0.01µF  [0603]  (hidden comment: GRM188R71H103KA01D)
C523  ValueDisplayed: 10µF  [0805_HV]  (hidden comment: GRM21BR61C106KE15L)
C524  ValueDisplayed: 0.01µF  [0603]  (hidden comment: GRM188R71H103KA01D)
C532  50V, 100nF  [0603_1.6x0.8x0.8mm_Reflow Soldering]
C533  50V, 100nF  [0603_1.6x0.8x0.8mm_Reflow Soldering]
C534  50V, 100nF  [0603_1.6x0.8x0.8mm_Reflow Soldering]
D19  SMBJ15CA  value 15V  [SMB-Bi]
D20  MBR130T1G  [SOD-123]
D21  value Green  [LTST-C191_Green]  (hidden comment: LTST-C191TGKT)
J55  RAPC722X  [CONN_RAPC722X]
L35  ValueDisplayed: 1000 ohm  [1806_HighSpeed]  (hidden comment: BLM41PG102SN1L)
L36  ValueDisplayed: 1000 ohm  [1806_HighSpeed]  (hidden comment: BLM41PG102SN1L)
L57  880Ω  [WE-CBF_1812_High Current]
L72  ValueDisplayed: 1000 ohm  [1806_HighSpeed]  (hidden comment: BLM41PG102SN1L)
L87  ValueDisplayed: 1000 ohm  [1806_HighSpeed]  (hidden comment: BLM41PG102SN1L)
L93  30Ω  [WE-CBF_1210_High Current]
L94  30Ω  [WE-CBF_1210_High Current]
L95  30Ω  [WE-CBF_1210_High Current]
L96  30Ω  [WE-CBF_1210_High Current]
Q3  CSD15571Q2  [DQK0006C]
R174  ValueDisplayed: 0  [1206]  (hidden comment: CRCW12060000Z0EA)
R222  ValueDisplayed: 0  [0603]  (hidden comment: CRCW06030000Z0EA)
R386  ValueDisplayed: 0  [0603]  (hidden comment: CRCW06030000Z0EA)
R387  ValueDisplayed: 0  [0603]  (hidden comment: CRCW06030000Z0EA)
R484  ValueDisplayed: 1.00M  [0603]  (hidden comment: CRCW06031M00FKEA)
R485  ValueDisplayed: 1.00k  [0603]  (hidden comment: CRCW06031K00FKEA)
R486  ValueDisplayed: 10.0k  [0603]  (hidden comment: CRCW060310K0FKEA)
R487  ValueDisplayed: 45.3k  [0603]  (hidden comment: CRCW060345K3FKEA)
R488  ValueDisplayed: 100k  [0603]  (hidden comment: CRCW0603100KFKEA)
R489  ValueDisplayed: 100k  [0402]  (hidden comment: CRCW0402100KFKED)
R490  ValueDisplayed: 11.0k  [0402]  (hidden comment: CRCW040211K0FKED)
R491  ValueDisplayed: 13.7k  [0402]  (hidden comment: CRCW040213K7FKED)
R492  ValueDisplayed: 8.06k  [0402]  (hidden comment: CRCW04028K06FKED)
R493  ValueDisplayed: 10.0k  [0603]  (hidden comment: CRCW060310K0FKEA)
R494  ValueDisplayed: 0  [0603]  (hidden comment: CRCW06030000Z0EA)
R495  ValueDisplayed: 0  [0402]  (hidden comment: CRCW04020000Z0ED)
R496  ValueDisplayed: 0  [0402]  (hidden comment: CRCW04020000Z0ED)
R497  ValueDisplayed: 0  [0402]  (hidden comment: CRCW04020000Z0ED)
R498  ValueDisplayed: 0  [0402]  (hidden comment: CRCW04020000Z0ED)
R499  ValueDisplayed: 0  [0402]  (hidden comment: CRCW04020000Z0ED)
R500  ValueDisplayed: 0  [0402]  (hidden comment: CRCW04020000Z0ED)
R614  ValueDisplayed: 0  [1206]  (hidden comment: CRCW12060000Z0EA)
S17  L101011MS02Q  [SW_ L101011MS02Q]  (value not drawn)
TP5  TP-025-SMT  [PROBE_POINT_30PAD]  (value not drawn)
TP11  TP-025-SMT  [PROBE_POINT_30PAD]  (value not drawn)
TP17  5000  [Keystone5000]  (value not drawn)
TP18  5000  [Keystone5000]  (value not drawn)
TP19  5012  [Keystone5012]  (value not drawn)
TP20  5001  [Keystone5001]  (value not drawn)
TP21  5000  [Keystone5000]  (value not drawn)
TP22  5000  [Keystone5000]  (value not drawn)
TP23  5000  [Keystone5000]  (value not drawn)
TP51  5001  [Keystone5001]  (value not drawn)
TP52  5001  [Keystone5001]  (value not drawn)
TP53  5001  [Keystone5001]  (value not drawn)
TP64  5001  [Keystone5001]  (value not drawn)
TP65  5001  [Keystone5001]  (value not drawn)
TP66  5001  [Keystone5001]  (value not drawn)
TP67  5001  [Keystone5001]  (value not drawn)
TP68  5001  [Keystone5001]  (value not drawn)
TP69  5001  [Keystone5001]  (value not drawn)
TP70  5001  [Keystone5001]  (value not drawn)
TP71  5001  [Keystone5001]  (value not drawn)
TP72  5001  [Keystone5001]  (value not drawn)
TP73  5001  [Keystone5001]  (value not drawn)
TP74  5001  [Keystone5001]  (value not drawn)
TP75  5001  [Keystone5001]  (value not drawn)
TP76  5001  [Keystone5001]  (value not drawn)
TP77  5015  [Testpoint_Keystone_Miniature]  (value not drawn)
TP81  TP-025-SMT  [PROBE_POINT_30PAD]  (value not drawn)
TP82  5015  [Testpoint_Keystone_Miniature]  (value not drawn)
TP87  5001  [Keystone5001]  (value not drawn)
TP88  5001  [Keystone5001]  (value not drawn)
TP89  5001  [Keystone5001]  (value not drawn)
TP90  5001  [Keystone5001]  (value not drawn)
TP91  5001  [Keystone5001]  (value not drawn)
U38  TPS259261DRCR  [DRC0010J]
U39  TPS82130SILR  [SIL0008D_SMD]
U40  NFM31PC276B0J3L  [Murata_NFM31P]  (value not drawn)
U41  TPS7A8400RGRR  [RGR0020A]

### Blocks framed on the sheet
3A: C516-C519 C522-C524 R222 R386 R387 R493-R500 TP81 TP82 U41

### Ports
LDO_PG_1P9V (out), PG_3P3V (in)

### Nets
12V: C477.1 C478.1 D20.1(K) R485.2 TP18.1 U38.6(OUT) U38.7(OUT) U38.8(OUT)
12V_DC: C479.1 D19.2 Q3.3(G) R484.2 S17.1 TP17.1 U38.3(VIN) U38.4(VIN) U38.5(VIN)
12VIN: L87.2 TP77.1
AGND: L93.1 L94.1 L95.1 L96.1 TP51.1 TP52.1 TP53.1 TP64.1  [also labelled AGND1, AGND2, AGND3, AGND4]
DGND: C134.2(-) C135.2 C136.2 C137.2 C138.2 C139.2 C140.2 C141.2 C142.2 C143.2 C144.2 C145.2 C146.2 C294.2(-) C295.2 C296.2 C297.2 C298.2 C299.2 C300.2 C301.2 C302.2 C303.2 C304.2 C305.2 C306.2 C482.2(-) C483.2 C484.2 C532.1 C533.1 C534.1 L93.2 L94.2 L95.2 L96.2 R174.2 TP65.1 TP66.1 TP67.1 TP68.1 TP69.1 TP70.1 TP71.1 TP72.1 TP73.1 TP74.1 TP75.1 TP76.1  [also labelled GND_ADC1, GND_ADC2, GND_PLL]
GND: C355.2 C477.2 C478.2 C480.2 C481.2 C494.2 C495.2 C496.1 C497.1 C498.1 C501.1 C516.2 C517.2 C518.2 C519.2 C523.2 C524.2 D20.2(A) D21.2(K) Q3.4(S) Q3.7(S) R174.1 R486.1 R488.1 R492.1 R495.1 R496.1 R497.1 R498.1 R499.1 R500.1 TP87.1 TP88.1 TP89.1 TP90.1 TP91.1 U38.11(PAD) U39.3(GND) U39.9(PAD) U40.2 U41.8(GND) U41.18(GND) U41.21(PAD)
GND1: C479.2 D19.1 J55.2 J55.3 Q3.1(D) Q3.2(D) Q3.5(D) Q3.6(D) Q3.8(D) TP20.1
V1P9V: C532.2 C533.2 C534.2 L35.1 L36.1 L72.1 TP22.1
V1P9V_IN: C496.2 C497.2 C498.2 R614.2 U40.3
VA1P9_ADC1: C134.1(+) C135.1 C136.1 C137.1 C138.1 C139.1 C140.1 C141.1 C142.1 C143.1 C144.1 C145.1 C146.1 L35.2 TP5.1
VA1P9_ADC2: C294.1(+) C295.1 C296.1 C297.1 C298.1 C299.1 C300.1 C301.1 C302.1 C303.1 C304.1 C305.1 C306.1 L36.2 TP11.1
VDDL19: C482.1(+) C483.1 C484.1 L72.2 TP23.1
EN/UVLO: C480.1 R484.1 R486.2 TP19.1 U38.2(EN/UVLO)
EN_A19V: R387.1 R489.1 U39.7(PG)
ILIM: R487.2 U38.10(ILIM)
LDO_PG_1P9V: R493.2 TP81.1 U41.4(PG) ; port LDO_PG_1P9V
PG_3P3V: R386.2 ; port PG_3P3V
NetC355_1: C355.1 C494.1 L87.1 U39.1(EN) U39.2(VIN)
NetC481_1: C481.1 U38.1(DV/DT)
NetC495_1: C495.1 L57.2 R489.2 R490.2 R491.2 TP21.1 U39.4(VOUT) U39.5(VOUT) U40.1
NetC501_2: C501.2 U39.8(SS/TR)
NetC516_1: C516.1 C517.1 C518.1 L57.1 R222.1 TP82.1 U41.15(IN) U41.16(IN) U41.17(IN)
NetC519_1: C519.1 C522.1 R493.1 R494.2 R614.1 U41.1(OUT) U41.19(OUT) U41.20(OUT)
NetC522_2: C522.2 U41.3(FB)
NetC523_1: C523.1 U41.12(BIAS)
NetC524_1: C524.1 U41.13(NR/SS)
NetD21_1: D21.1(A) R485.1
NetJ55_1: J55.1 S17.2
NetR222_2: R222.2 R386.1 R387.2 U41.14(EN)
NetR487_1: R487.1 R488.2
NetR490_1: R490.1 R491.1 R492.2 U39.6(FB)
NetR494_1: R494.1 U41.2(SNS)
NetR495_2: R495.2 U41.11(1.6_V)
NetR496_2: R496.2 U41.10(800_mV)
NetR497_2: R497.2 U41.9(400_mV)
NetR498_2: R498.2 U41.7(200_mV)
NetR499_2: R499.2 U41.6(100_mV)
NetR500_2: R500.2 U41.5(50_mV)

Not connected (* = marked no-connect by the designer): U38 9(NC)

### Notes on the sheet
- (near R488) RT - SHORT  =2.1A
  RB - SHORT =3.1A
  RT,RB = STUFF = 5.1A
- +1.9V  POWER RAIL
- Fsw = 2 MHz
- Build on TIDA-01022-E3 PCB and power solution used from TIDA-01027

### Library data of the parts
C134 C294 C482 = 293D106X0010B2TE3: CAP, TA, 10 µF, 10 V, +/- 20%, 2.5 ohm, SMD; Manufacturer: Vishay-Sprague; Polarized: Y; CompType: Capacitor; Value: 10uF; U/M: EA; Cap_F: 0.00001; Tolerance_%: 20; Value1: 2.5 ohm; VDC_V: 10; Value2: 10V; ESR_ohm: 2.5; IRMS_A: 0.18; TaMin_C: -55; TaMax_C: 125; Cap_Case: B; SizeAreaWB_mm2: 17.1; SizeArea_mm2: 9.8; SizeX_mm: 3.5; SizeY_mm: 2.8; SizeZ_mm: 2.1; AEC Category: Q200
C135-C146 C295-C306 C483 = GRM033C71A104KE14D: CAP, CERM, 0.1 µF, 10 V, +/- 10%, X7S, 0201; Manufacturer: MuRata; Polarized: N; CompType: Capacitor; Value: 0.1uF; U/M: EA; Cap_F: 0.0000001; Tolerance_%: 10; Value1: Unknown; Value2: 10V; TaMin_C: -55; TaMax_C: 125; SizeArea_mm2: 0.18; SizeAreaWB_mm2: 2.08; SizeX_mm: 0.6; SizeY_mm: 0.3; SizeZ_mm: 0.26; AEC Category: Q200
C355 = GRM1555C1H471JA01D: CAP, CERM, 470 pF, 50 V, +/- 5%, C0G/NP0, 0402; Manufacturer: MuRata; Polarized: N; CompType: Capacitor; Value: 470pF; U/M: EA; Cap_F: 0.00000000047; Tolerance_%: 5; Value1: Unknown; VDC_V: 50; Value2: 50V; TaMin_C: -55; TaMax_C: 125; SizeArea_mm2: 0.5; SizeAreaWB_mm2: 3; SizeX_mm: 1; SizeZ_mm: 0.6; AEC Category: Q200
C477-C479 = 08053D105KAT2A: CAP, CERM, 1 µF, 25 V, +/- 10%, X5R, 0805; Manufacturer: AVX; Polarized: N; CompType: Capacitor; Value: 1uF; U/M: EA; Cap_F: 0.000001; Tolerance_%: 10; ESR_ohm: 0.012; Value1: 0.012 ohm; VDC_V: 25; Value2: 25V; TaMin_C: -55; TaMax_C: 85; Cap_Case: 0805; SizeArea_mm2: 2.5; SizeAreaWB_mm2: 6.75; SizeX_mm: 2; SizeY_mm: 1.25; SizeZ_mm: 1.45; AEC Category: Q200
C480 C481 = 06031C102MAT2A: CAP, CERM, 1000 pF, 100 V, +/- 20%, X7R, 0603; Manufacturer: AVX; Polarized: N; CompType: Capacitor; Value: 1000pF; U/M: EA; Cap_F: 0.000000001; Tolerance_%: 20; ESR_ohm: 0.276; Value1: 0.276 ohm; VDC_V: 100; Value2: 100V; TaMin_C: -55; TaMax_C: 125; SizeArea_mm2: 1.28; SizeAreaWB_mm2: 4.68; SizeX_mm: 1.6; SizeY_mm: 0.8; SizeZ_mm: 1; AEC Category: Q200
C484 = C1608X5R1A105K080AC: as C476 on sheet TIDA-01022-E3_FMC+CONN2_1
C494 C496-C498 = C3216X7R1E106M160AE: CAP, CERM, 10 µF, 25 V, +/- 20%, X7R, 1206_190; Manufacturer: TDK; Polarized: N; CompType: Capacitor; Value: 10uF; U/M: EA; Cap_F: 0.00001; Tolerance_%: 20; Value1: Unknown; VDC_V: 25; Value2: 25V; TaMin_C: -55; TaMax_C: 125; Cap_Case: 1206; SizeArea_mm2: 5.12; SizeAreaWB_mm2: 10.92; SizeX_mm: 3.2; SizeY_mm: 1.6; SizeZ_mm: 1.9; AEC Category: Q200
C495 = JMK212BJ226MG-T: CAP, CERM, 22 µF, 6.3 V, +/- 20%, X5R, 0805; Manufacturer: Taiyo Yuden; Polarized: N; CompType: Capacitor; Value: 22uF; U/M: EA; Cap_F: 0.000022; Tolerance_%: 20; Value1: Unknown; VDC_V: 6.3; Value2: 6.3V; TaMin_C: -55; TaMax_C: 85; Cap_Case: 0805; SizeArea_mm2: 2.5; SizeAreaWB_mm2: 6.75; SizeX_mm: 2; SizeY_mm: 1.25; SizeZ_mm: 1.45; AEC Category: Q200
C501 = GRM1885C1H332JA01D: CAP, CERM, 3300 pF, 50 V, +/- 5%, C0G/NP0, 0603; Manufacturer: MuRata; Polarized: N; CompType: Capacitor; Value: 3300pF; U/M: EA; Cap_F: 0.0000000033; Tolerance_%: 5; Value1: Unknown; VDC_V: 50; Value2: 50V; TaMin_C: -55; TaMax_C: 125; SizeArea_mm2: 1.28; SizeAreaWB_mm2: 4.68; SizeX_mm: 1.6; SizeY_mm: 0.8; SizeZ_mm: 1; AEC Category: Q200
C516 C517 C523 = GRM21BR61C106KE15L: CAP, CERM, 10 µF, 16 V, +/- 10%, X5R, 0805; Manufacturer: MuRata; Polarized: N; CompType: Capacitor; Value: 10uF; U/M: EA; Cap_F: 0.00001; Tolerance_%: 10; ESR_ohm: 0.008; Value1: 0.008 ohm; VDC_V: 16; Value2: 16V; TaMin_C: -55; TaMax_C: 85; Cap_Case: 0805; SizeArea_mm2: 2.5; SizeAreaWB_mm2: 6.75; SizeX_mm: 2; SizeY_mm: 1.25; SizeZ_mm: 1.45; AEC Category: Q200
C518 C519 = GRM219R60G476ME44D: CAP, CERM, 47 µF, 4 V, +/- 20%, X5R, 0805; Manufacturer: MuRata; Polarized: N; CompType: Capacitor; Value: 47uF; U/M: EA; Cap_F: 0.000047; Tolerance_%: 20; Value1: Unknown; VDC_V: 4; Value2: 4V; TaMin_C: -55; TaMax_C: 85; Cap_Case: 0805; SizeArea_mm2: 2.5; SizeAreaWB_mm2: 6.75; SizeX_mm: 2; SizeY_mm: 1.25; SizeZ_mm: 1.45; AEC Category: Q200
C522 C524 = GRM188R71H103KA01D: CAP, CERM, 0.01 µF, 50 V, +/- 10%, X7R, 0603; Manufacturer: MuRata; Polarized: N; CompType: Capacitor; Value: 0.01uF; U/M: EA; Cap_F: 0.00000001; Tolerance_%: 10; Value1: Unknown; VDC_V: 50; Value2: 50V; TaMin_C: -55; TaMax_C: 125; SizeArea_mm2: 1.28; SizeAreaWB_mm2: 4.68; SizeX_mm: 1.6; SizeY_mm: 0.8; SizeZ_mm: 1; AEC Category: Q200
C532-C534 = 885012206095: WCAP-CSGP Ceramic Capacitors, 0603, X7R, 50V, 100nF; Rated Voltage: 50V DC
D19 = SMBJ15CA: Diode, TVS, Bi, 15 V, 24.4 Vc, SMB; Manufacturer: Fairchild Semiconductor; U/M: EA; Vr_V: 15; Value1: W; AEC Category: Q101
D20 = MBR130T1G: Diode, Schottky, 30 V, 1 A, SOD-123; Manufacturer: ON Semiconductor; U/M: EA; Vf_V: 0.47; Value: 30V; Value1: 1A; Value2: 0.47V; Io_A: 1; Vr_V: 30; TJmax_C: 125; RJC_CperW: 108; SizeAreaWB_mm2: 13.095; SizeArea_mm2: 6.545; SizeX_mm: 3.85; SizeY_mm: 1.7; SizeZ_mm: 1.35; AEC Category: Q101
D21 = LTST-C191TGKT: LED, Green, SMD; Manufacturer: Lite-On; Type: InGaN; Vf_V: 3.2; Value2: 3.2V; Io_A: 0.02; Value1: W; U/M: EA
J55 = RAPC722X: Power Jack, mini, 2.1mm OD, R/A, TH; Manufacturer: Switchcraft; SymbolCreator: a0799628
L35 L36 L72 L87 = BLM41PG102SN1L: Ferrite Bead, 1000 ohm @ 100 MHz, 1.5 A, 1806; Manufacturer: MuRata; Imax_A: 1.5; DCR_ohm: 0.09; Value1: 0.09 ohm; Value2: 1.5A; SizeAreaWB_mm2: 14.3; SizeArea_mm2: 7.2; SizeX_mm: 4.5; SizeY_mm: 1.6; SizeZ_mm: 1.85; ZTyp@100MHz_Ohm: 1000
L57 = WE-CBF, 74279252: WE-CBF SMD EMI Suppression Ferrite Bead, 1812, 880Ω; Type: High Current
L93-L96 = WE-CBF, 742792310: WE-CBF SMD EMI Suppression Ferrite Bead, 1210, 30Ω; Type: High Current
Q3 = CSD15571Q2: MOSFET, N-CH, 20 V, 10 A, DQK0006C (WSON-6); Manufacturer: Texas Instruments; Alternate Manufacturer: None; U/M: EA; ChType: N; Value: 20V; VdsMax_V: 20; Value1: 19.2 ohm; Rdson45_ohm: 19.2; Value2: 2.5 nC; QgTyp_nC: 2.5; IdsMax_A: 10; SizeAreaWB_mm2: 9; SizeArea_mm2: 4; SizeX_mm: 2; SizeZ_mm: 0.8; AEC Category: Q101
R174 = CRCW12060000Z0EA: RES, 0, 5%, 0.25 W, 1206; Manufacturer: Vishay-Dale; CompType: Resistor; Value: 0; Value_Code: 0000; Tolerance_%: 5; Power_W: 0.25; Value2: 0.25W; VDC_V: 200; TempCo: 200 ppm/C; SizeArea_mm2: 5.12; SizeX_mm: 3.2; SizeY_mm: 1.6; SizeZ_mm: 1.35; EIA_Code: E24; U/M: EA; AEC Category: Q200; Green_Lifecycle: Active; Green_REACh: Passed
R222 R386 R387 = CRCW06030000Z0EA: RES, 0, 5%, 0.1 W, 0603; Manufacturer: Vishay-Dale; CompType: Resistor; Value: 0; Value_Code: 0000; Tolerance_%: 5; Power_W: 0.1; Value2: 0.1W; VDC_V: 75; TempCo: 200 ppm/C; SizeArea_mm2: 1.28; SizeX_mm: 1.6; SizeY_mm: 0.8; SizeZ_mm: 1; EIA_Code: E24; U/M: EA; AEC Category: Q200; Green_Lifecycle: Active; Green_REACh: Passed
R484 = CRCW06031M00FKEA: RES, 1.00 M, 1%, 0.1 W, 0603; Manufacturer: Vishay-Dale; CompType: Resistor; Value: 1.00Meg; Res_ohm: 1000000; Value_Code: 1M00; Tolerance_%: 1; Power_W: 0.1; Value2: 0.1W; VDC_V: 75; TempCo: 100 ppm/C; SizeArea_mm2: 1.28; SizeX_mm: 1.6; SizeY_mm: 0.8; EIA_Code: E96; U/M: EA; AEC Category: Q200
R485 = CRCW06031K00FKEA: RES, 1.00 k, 1%, 0.1 W, 0603; Manufacturer: Vishay-Dale; CompType: Resistor; Value: 1.00k; Res_ohm: 1000; Value_Code: 1k00; Tolerance_%: 1; Power_W: 0.1; Value2: 0.1W; VDC_V: 75; TempCo: 100 ppm/C; SizeArea_mm2: 1.28; SizeX_mm: 1.6; SizeY_mm: 0.8; EIA_Code: E96; U/M: EA; AEC Category: Q200
R486 R493 = CRCW060310K0FKEA: RES, 10.0 k, 1%, 0.1 W, 0603; Manufacturer: Vishay-Dale; CompType: Resistor; Value: 10.0k; Res_ohm: 10000; Value_Code: 10k0; Tolerance_%: 1; Power_W: 0.1; Value2: 0.1W; VDC_V: 75; TempCo: 100 ppm/C; SizeArea_mm2: 1.28; SizeX_mm: 1.6; SizeY_mm: 0.8; EIA_Code: E96; U/M: EA; AEC Category: Q200
R487 = CRCW060345K3FKEA: RES, 45.3 k, 1%, 0.1 W, 0603; Manufacturer: Vishay-Dale; CompType: Resistor; Value: 45.3k; Res_ohm: 45300; Value_Code: 45k3; Tolerance_%: 1; Power_W: 0.1; Value2: 0.1W; VDC_V: 75; TempCo: 100 ppm/C; SizeArea_mm2: 1.28; SizeX_mm: 1.6; SizeY_mm: 0.8; EIA_Code: E96; U/M: EA; AEC Category: Q200
R488 = CRCW0603100KFKEA: RES, 100 k, 1%, 0.1 W, 0603; Manufacturer: Vishay-Dale; CompType: Resistor; Value: 100k; Res_ohm: 100000; Tolerance_%: 1; Power_W: 0.1; Value2: 0.1W; VDC_V: 75; TempCo: 100 ppm/C; SizeArea_mm2: 1.28; SizeX_mm: 1.6; SizeY_mm: 0.8; EIA_Code: E96; U/M: EA; AEC Category: Q200
R489 = CRCW0402100KFKED: RES, 100 k, 1%, 0.063 W, 0402; Manufacturer: Vishay-Dale; CompType: Resistor; Value: 100k; Res_ohm: 100000; Tolerance_%: 1; Power_W: 0.063; Value2: 0.063W; VDC_V: 50; TempCo: 100 ppm/C; SizeArea_mm2: 0.5; SizeZ_mm: 0.6; EIA_Code: E96; U/M: EA; AEC Category: Q200
R490 = CRCW040211K0FKED: RES, 11.0 k, 1%, 0.063 W, 0402; Manufacturer: Vishay-Dale; CompType: Resistor; Value: 11.0k; Res_ohm: 11000; Value_Code: 11k0; Tolerance_%: 1; Power_W: 0.063; Value2: 0.063W; VDC_V: 50; TempCo: 100 ppm/C; SizeArea_mm2: 0.5; SizeZ_mm: 0.6; EIA_Code: E96; U/M: EA; AEC Category: Q200
R491 = CRCW040213K7FKED: RES, 13.7 k, 1%, 0.063 W, 0402; Manufacturer: Vishay-Dale; CompType: Resistor; Value: 13.7k; Res_ohm: 13700; Value_Code: 13k7; Tolerance_%: 1; Power_W: 0.063; Value2: 0.063W; VDC_V: 50; TempCo: 100 ppm/C; SizeArea_mm2: 0.5; SizeZ_mm: 0.6; EIA_Code: E96; U/M: EA; AEC Category: Q200
R492 = CRCW04028K06FKED: RES, 8.06 k, 1%, 0.063 W, 0402; Manufacturer: Vishay-Dale; CompType: Resistor; Value: 8.06k; Res_ohm: 8060; Value_Code: 8k06; Tolerance_%: 1; Power_W: 0.063; Value2: 0.063W; VDC_V: 50; TempCo: 100 ppm/C; SizeArea_mm2: 0.5; SizeZ_mm: 0.6; EIA_Code: E96; U/M: EA; AEC Category: Q200
R494 = CRCW06030000Z0EA: RES, 0, 5%, 0.1 W, 0603; Manufacturer: Vishay-Dale; CompType: Resistor; Value: 0; Value_Code: 0000; Tolerance_%: 5; Power_W: 0.1; Value2: 0.1W; VDC_V: 75; TempCo: 200 ppm/C; SizeArea_mm2: 1.28; SizeX_mm: 1.6; SizeY_mm: 0.8; SizeZ_mm: 1; EIA_Code: E24; U/M: EA; AEC Category: Q200
R495-R500 = CRCW04020000Z0ED: as R479 on sheet TIDA-01022-E3_FMC+CONN2_1
R614 = CRCW12060000Z0EA: RES, 0, 5%, 0.25 W, 1206; Manufacturer: Vishay-Dale; CompType: Resistor; Value: 0; Value_Code: 0000; Tolerance_%: 5; Power_W: 0.25; Value2: 0.25W; VDC_V: 200; TempCo: 200 ppm/C; SizeArea_mm2: 5.12; SizeX_mm: 3.2; SizeY_mm: 1.6; SizeZ_mm: 1.35; EIA_Code: E24; U/M: EA; AEC Category: Q200
S17 = L101011MS02Q: SWITCH SLIDE SPST 4A PCB, TH; Manufacturer: C&K Components; Symbol Creator: a0411947; VDC_V: 125; SwitchFunction: Off-On; PositionCount: 1; CurrentRating_mA: 4000
TP5 TP11 TP81 = TP-025-SMT: Test Point, O.025"; Manufacturer: STD; Value: STD
TP17 TP18 TP21 TP22 = 5000: as 3P3V_RX2 on sheet TIDA-01022-E3_FMC+CONN2_1
TP19 = 5012: Test Point, Multipurpose, White, TH; Manufacturer: Keystone; CompType: Test Point Loop; ContactFinish: Silver
TP20 TP51-TP53 TP64-TP76 TP87-TP91 = 5001: Test Point, Miniature, Black, TH; Manufacturer: Keystone; CompType: Test Point Loop; ContactFinish: Silver; Green_Lifecycle: Active; Green_REACh: Passed
TP23 = 5000: Test Point, Miniature, Red, TH; Manufacturer: Keystone; CompType: Test Point Loop; ContactFinish: Silver
TP77 TP82 = 5015: Test Point, Miniature, SMT; Manufacturer: Keystone; CompType: Test Point Loop; Green_Lifecycle: Active; Green_REACh: Passed
U38 = TPS259261DRCR: 12V, 5A, 30mΩ eFuse with Adjustable +/-15% Accurate Current Limit, DRC0010J (VSON-10); Alternate PartNumber: TPS259261DRCT; Manufacturer: Texas Instruments; SymbolCreator: Altium; SizeArea_mm2: 9; SizeAreaWB_mm2: 16; SizeX_mm: 3; SizeZ_mm: 1; CompType: IC; U/M: EA
U39 = TPS82130SILR: 3-A 17V Step-down Converter Module with Integrated Inductor, SIL0008D (uSIP-8); Alternate PartNumber: TPS82130SILT; Manufacturer: Texas Instruments; SymbolCreator: Altium; SizeArea_mm2: 12.25; SizeAreaWB_mm2: 20.25; SizeX_mm: 3.5; SizeZ_mm: 1.53; CompType: IC; U/M: EA
U40 = NFM31PC276B0J3L: FILTER LC HIGH FREQ 27uF 1206; Manufacturer: MuRata; SymbolCreator: Altium
U41 = TPS7A8400RGRR: High-Current (3 A), High-Accuracy (1%), Low-Noise (4.4 μVRMS), LDO Voltage Regulator, RGR0020A (VQFN-20); Alternate PartNumber: TPS7A8400RGRT; Manufacturer: Texas Instruments; SymbolCreator: a0411947; SizeArea_mm2: 12.25; SizeAreaWB_mm2: 20.25; SizeX_mm: 3.5; SizeZ_mm: 1; CompType: IC; U/M: EA

## Sheet TIDA-01022-E3_Power2.SchDoc: Power Supplies
size 431 x 279 mm; Date: Not shown in title block; ApprovedBy: Not shown in title block; CheckedBy: Not shown in title block; Author: Not shown in title block; CompanyName: Not shown in title block; DrawnBy: Avinash N; Engineer: Not shown in title block; Organization: Not shown in title block; Address1: Not shown in title block; Address2: Not shown in title block; Address3: Not shown in title block; Address4: Not shown in title block; DocumentNumber: 1; Revision: Use project parameter SCH_Rev; SheetNumber: 22; SheetTotal: 26; PageSetup: Record=PageOptions¦CenterHorizontal=True¦CenterVertical=True¦PrintScale=1.00¦XCorrection=1.00¦YCorrection=1.00¦PrintKind=0¦BorderSize=5000000¦LeftOffset=0¦BottomOffset=0¦Orientation=2¦PaperLength=1000¦PaperWidth=1000¦Scale=100¦PaperSource=15¦PrintQuality=600¦MediaType=1¦DitherType=10¦PaperKind=Letter¦PrintScaleMode=1

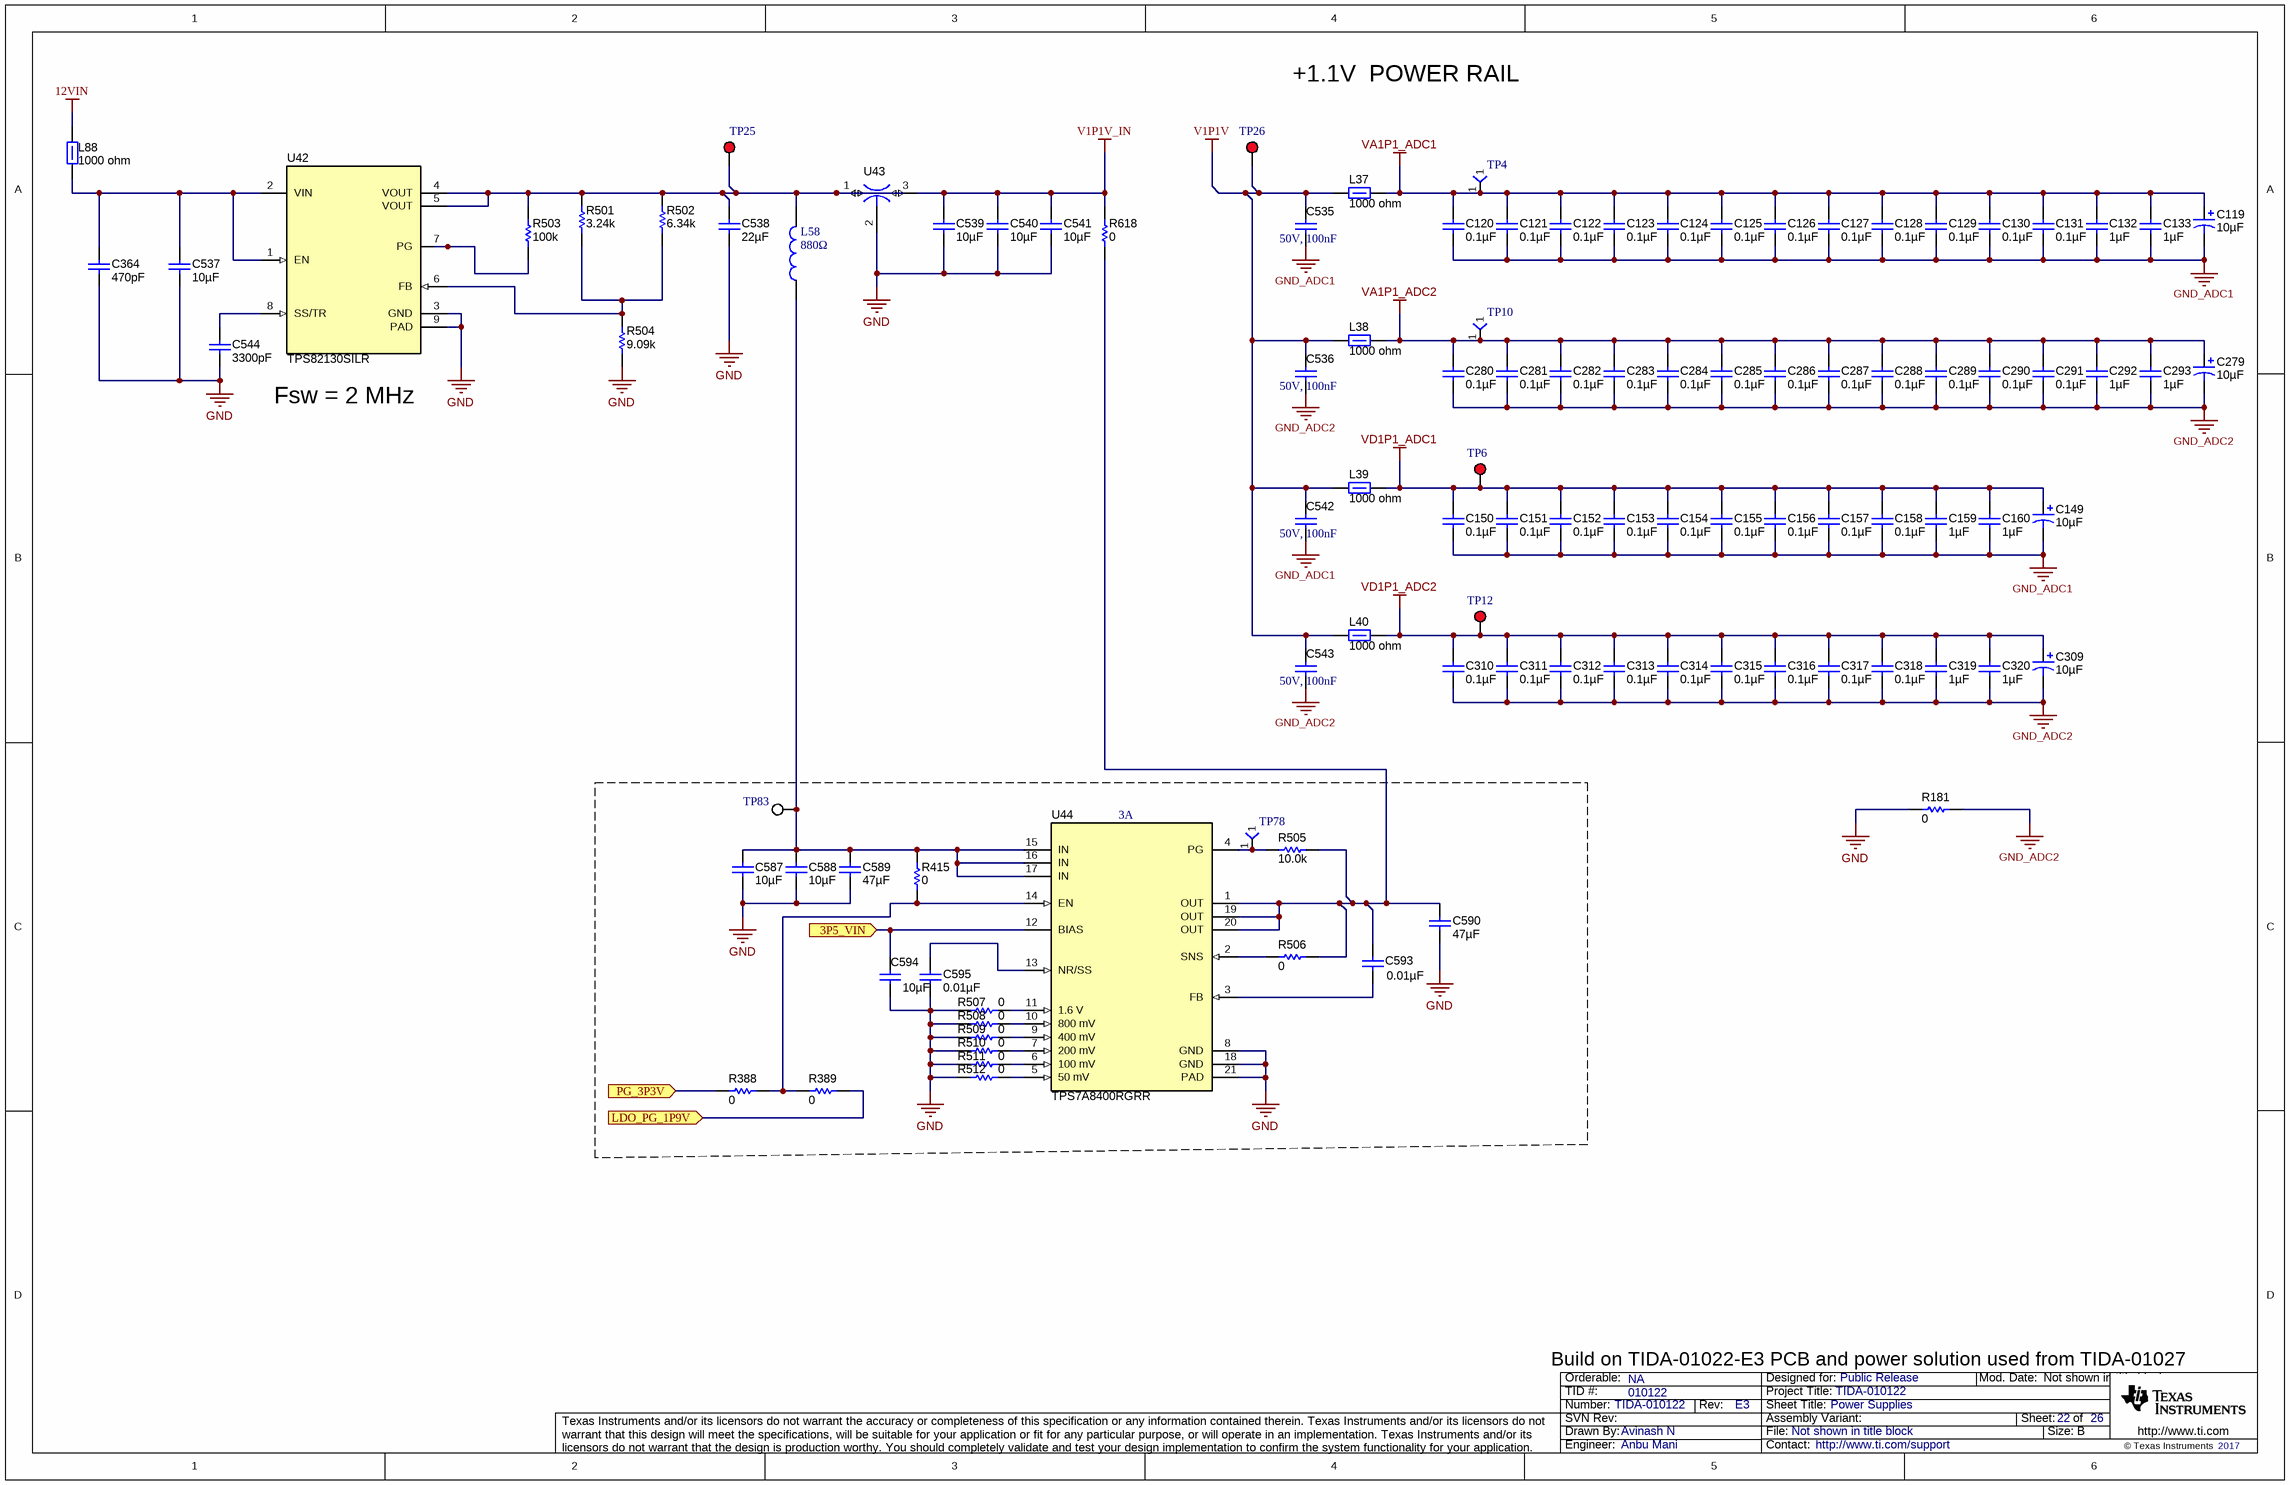
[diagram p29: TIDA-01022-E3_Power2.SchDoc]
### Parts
C119  ValueDisplayed: 10µF  [3528-21]  (hidden comment: 293D106X0010B2TE3)
C120  ValueDisplayed: 0.1µF  [0201]  (hidden comment: GRM033C71A104KE14D)
C121  ValueDisplayed: 0.1µF  [0201]  (hidden comment: GRM033C71A104KE14D)
C122  ValueDisplayed: 0.1µF  [0201]  (hidden comment: GRM033C71A104KE14D)
C123  ValueDisplayed: 0.1µF  [0201]  (hidden comment: GRM033C71A104KE14D)
C124  ValueDisplayed: 0.1µF  [0201]  (hidden comment: GRM033C71A104KE14D)
C125  ValueDisplayed: 0.1µF  [0201]  (hidden comment: GRM033C71A104KE14D)
C126  ValueDisplayed: 0.1µF  [0201]  (hidden comment: GRM033C71A104KE14D)
C127  ValueDisplayed: 0.1µF  [0201]  (hidden comment: GRM033C71A104KE14D)
C128  ValueDisplayed: 0.1µF  [0201]  (hidden comment: GRM033C71A104KE14D)
C129  ValueDisplayed: 0.1µF  [0201]  (hidden comment: GRM033C71A104KE14D)
C130  ValueDisplayed: 0.1µF  [0201]  (hidden comment: GRM033C71A104KE14D)
C131  ValueDisplayed: 0.1µF  [0201]  (hidden comment: GRM033C71A104KE14D)
C132  ValueDisplayed: 1µF  [0603]  (hidden comment: C1608X5R1A105K080AC)
C133  ValueDisplayed: 1µF  [0603]  (hidden comment: C1608X5R1A105K080AC)
C149  ValueDisplayed: 10µF  [3528-21]  (hidden comment: 293D106X0010B2TE3)
C150  ValueDisplayed: 0.1µF  [0201]  (hidden comment: GRM033C71A104KE14D)
C151  ValueDisplayed: 0.1µF  [0201]  (hidden comment: GRM033C71A104KE14D)
C152  ValueDisplayed: 0.1µF  [0201]  (hidden comment: GRM033C71A104KE14D)
C153  ValueDisplayed: 0.1µF  [0201]  (hidden comment: GRM033C71A104KE14D)
C154  ValueDisplayed: 0.1µF  [0201]  (hidden comment: GRM033C71A104KE14D)
C155  ValueDisplayed: 0.1µF  [0201]  (hidden comment: GRM033C71A104KE14D)
C156  ValueDisplayed: 0.1µF  [0201]  (hidden comment: GRM033C71A104KE14D)
C157  ValueDisplayed: 0.1µF  [0201]  (hidden comment: GRM033C71A104KE14D)
C158  ValueDisplayed: 0.1µF  [0201]  (hidden comment: GRM033C71A104KE14D)
C159  ValueDisplayed: 1µF  [0603]  (hidden comment: C1608X5R1A105K080AC)
C160  ValueDisplayed: 1µF  [0603]  (hidden comment: C1608X5R1A105K080AC)
C279  ValueDisplayed: 10µF  [3528-21]  (hidden comment: 293D106X0010B2TE3)
C280  ValueDisplayed: 0.1µF  [0201]  (hidden comment: GRM033C71A104KE14D)
C281  ValueDisplayed: 0.1µF  [0201]  (hidden comment: GRM033C71A104KE14D)
C282  ValueDisplayed: 0.1µF  [0201]  (hidden comment: GRM033C71A104KE14D)
C283  ValueDisplayed: 0.1µF  [0201]  (hidden comment: GRM033C71A104KE14D)
C284  ValueDisplayed: 0.1µF  [0201]  (hidden comment: GRM033C71A104KE14D)
C285  ValueDisplayed: 0.1µF  [0201]  (hidden comment: GRM033C71A104KE14D)
C286  ValueDisplayed: 0.1µF  [0201]  (hidden comment: GRM033C71A104KE14D)
C287  ValueDisplayed: 0.1µF  [0201]  (hidden comment: GRM033C71A104KE14D)
C288  ValueDisplayed: 0.1µF  [0201]  (hidden comment: GRM033C71A104KE14D)
C289  ValueDisplayed: 0.1µF  [0201]  (hidden comment: GRM033C71A104KE14D)
C290  ValueDisplayed: 0.1µF  [0201]  (hidden comment: GRM033C71A104KE14D)
C291  ValueDisplayed: 0.1µF  [0201]  (hidden comment: GRM033C71A104KE14D)
C292  ValueDisplayed: 1µF  [0603]  (hidden comment: C1608X5R1A105K080AC)
C293  ValueDisplayed: 1µF  [0603]  (hidden comment: C1608X5R1A105K080AC)
C309  ValueDisplayed: 10µF  [3528-21]  (hidden comment: 293D106X0010B2TE3)
C310  ValueDisplayed: 0.1µF  [0201]  (hidden comment: GRM033C71A104KE14D)
C311  ValueDisplayed: 0.1µF  [0201]  (hidden comment: GRM033C71A104KE14D)
C312  ValueDisplayed: 0.1µF  [0201]  (hidden comment: GRM033C71A104KE14D)
C313  ValueDisplayed: 0.1µF  [0201]  (hidden comment: GRM033C71A104KE14D)
C314  ValueDisplayed: 0.1µF  [0201]  (hidden comment: GRM033C71A104KE14D)
C315  ValueDisplayed: 0.1µF  [0201]  (hidden comment: GRM033C71A104KE14D)
C316  ValueDisplayed: 0.1µF  [0201]  (hidden comment: GRM033C71A104KE14D)
C317  ValueDisplayed: 0.1µF  [0201]  (hidden comment: GRM033C71A104KE14D)
C318  ValueDisplayed: 0.1µF  [0201]  (hidden comment: GRM033C71A104KE14D)
C319  ValueDisplayed: 1µF  [0603]  (hidden comment: C1608X5R1A105K080AC)
C320  ValueDisplayed: 1µF  [0603]  (hidden comment: C1608X5R1A105K080AC)
C364  ValueDisplayed: 470pF  [0402]  (hidden comment: GRM1555C1H471JA01D)
C535  50V, 100nF  [0603_1.6x0.8x0.8mm_Reflow Soldering]
C536  50V, 100nF  [0603_1.6x0.8x0.8mm_Reflow Soldering]
C537  ValueDisplayed: 10µF  [1206_190]  (hidden comment: C3216X7R1E106M160AE)
C538  ValueDisplayed: 22µF  [0805_HV]  (hidden comment: JMK212BJ226MG-T)
C539  ValueDisplayed: 10µF  [1206_190]  (hidden comment: C3216X7R1E106M160AE)
C540  ValueDisplayed: 10µF  [1206_190]  (hidden comment: C3216X7R1E106M160AE)
C541  ValueDisplayed: 10µF  [1206_190]  (hidden comment: C3216X7R1E106M160AE)
C542  50V, 100nF  [0603_1.6x0.8x0.8mm_Reflow Soldering]
C543  50V, 100nF  [0603_1.6x0.8x0.8mm_Reflow Soldering]
C544  ValueDisplayed: 3300pF  [0603]  (hidden comment: GRM1885C1H332JA01D)
C587  ValueDisplayed: 10µF  [0805_HV]  (hidden comment: GRM21BR61C106KE15L)
C588  ValueDisplayed: 10µF  [0805_HV]  (hidden comment: GRM21BR61C106KE15L)
C589  ValueDisplayed: 47µF  [0805_HV]  (hidden comment: GRM219R60G476ME44D)
C590  ValueDisplayed: 47µF  [0805_HV]  (hidden comment: GRM219R60G476ME44D)
C593  ValueDisplayed: 0.01µF  [0603]  (hidden comment: GRM188R71H103KA01D)
C594  ValueDisplayed: 10µF  [0805_HV]  (hidden comment: GRM21BR61C106KE15L)
C595  ValueDisplayed: 0.01µF  [0603]  (hidden comment: GRM188R71H103KA01D)
L37  ValueDisplayed: 1000 ohm  [1806_HighSpeed]  (hidden comment: BLM41PG102SN1L)
L38  ValueDisplayed: 1000 ohm  [1806_HighSpeed]  (hidden comment: BLM41PG102SN1L)
L39  ValueDisplayed: 1000 ohm  [1806_HighSpeed]  (hidden comment: BLM41PG102SN1L)
L40  ValueDisplayed: 1000 ohm  [1806_HighSpeed]  (hidden comment: BLM41PG102SN1L)
L58  880Ω  [WE-CBF_1812_High Current]
L88  ValueDisplayed: 1000 ohm  [1806_HighSpeed]  (hidden comment: BLM41PG102SN1L)
R181  ValueDisplayed: 0  [1206]  (hidden comment: CRCW12060000Z0EA)
R388  ValueDisplayed: 0  [0603]  (hidden comment: CRCW06030000Z0EA)
R389  ValueDisplayed: 0  [0603]  (hidden comment: CRCW06030000Z0EA)
R415  ValueDisplayed: 0  [0603]  (hidden comment: CRCW06030000Z0EA)
R501  ValueDisplayed: 3.24k  [0402]  (hidden comment: CRCW04023K24FKED)
R502  ValueDisplayed: 6.34k  [0402]  (hidden comment: CRCW04026K34FKED)
R503  ValueDisplayed: 100k  [0402]  (hidden comment: CRCW0402100KFKED)
R504  ValueDisplayed: 9.09k  [0402]  (hidden comment: CRCW04029K09FKED)
R505  ValueDisplayed: 10.0k  [0603]  (hidden comment: CRCW060310K0FKEA)
R506  ValueDisplayed: 0  [0603]  (hidden comment: CRCW06030000Z0EA)
R507  ValueDisplayed: 0  [0402]  (hidden comment: CRCW04020000Z0ED)
R508  ValueDisplayed: 0  [0402]  (hidden comment: CRCW04020000Z0ED)
R509  ValueDisplayed: 0  [0402]  (hidden comment: CRCW04020000Z0ED)
R510  ValueDisplayed: 0  [0402]  (hidden comment: CRCW04020000Z0ED)
R511  ValueDisplayed: 0  [0402]  (hidden comment: CRCW04020000Z0ED)
R512  ValueDisplayed: 0  [0402]  (hidden comment: CRCW04020000Z0ED)
R618  ValueDisplayed: 0  [1206]  (hidden comment: CRCW12060000Z0EA)
TP4  TP-025-SMT  [PROBE_POINT_30PAD]  (value not drawn)
TP6  5000  [Keystone5000]  (value not drawn)
TP10  TP-025-SMT  [PROBE_POINT_30PAD]  (value not drawn)
TP12  5000  [Keystone5000]  (value not drawn)
TP25  5000  [Keystone5000]  (value not drawn)
TP26  5000  [Keystone5000]  (value not drawn)
TP78  TP-025-SMT  [PROBE_POINT_30PAD]  (value not drawn)
TP83  5015  [Testpoint_Keystone_Miniature]  (value not drawn)
U42  TPS82130SILR  [SIL0008D_SMD]
U43  NFM31PC276B0J3L  [Murata_NFM31P]  (value not drawn)
U44  TPS7A8400RGRR  [RGR0020A]

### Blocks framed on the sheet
3A: C587-C590 C593-C595 R388 R389 R415 R505-R512 TP78 TP83 U44

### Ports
3P5_VIN (in), LDO_PG_1P9V (in), PG_3P3V (in)

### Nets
12VIN: L88.2
GND: C364.2 C537.2 C538.2 C539.1 C540.1 C541.1 C544.1 C587.2 C588.2 C589.2 C590.2 C594.2 C595.2 R181.1 R504.1 R507.1 R508.1 R509.1 R510.1 R511.1 R512.1 U42.3(GND) U42.9(PAD) U43.2 U44.8(GND) U44.18(GND) U44.21(PAD)
GND_ADC1: C119.2(-) C120.2 C121.2 C122.2 C123.2 C124.2 C125.2 C126.2 C127.2 C128.2 C129.2 C130.2 C131.2 C132.2 C133.2 C149.2(-) C150.2 C151.2 C152.2 C153.2 C154.2 C155.2 C156.2 C157.2 C158.2 C159.2 C160.2 C279.2(-) C280.2 C281.2 C282.2 C283.2 C284.2 C285.2 C286.2 C287.2 C288.2 C289.2 C290.2 C291.2 C292.2 C293.2 C309.2(-) C310.2 C311.2 C312.2 C313.2 C314.2 C315.2 C316.2 C317.2 C318.2 C319.2 C320.2 C535.1 C536.1 C542.1 C543.1 R181.2  [also labelled GND_ADC2]  [project net DGND]
V1P1V: C535.2 C536.2 C542.2 C543.2 L37.1 L38.1 L39.1 L40.1 TP26.1
V1P1V_IN: C539.2 C540.2 C541.2 R618.2 U43.3
VA1P1_ADC1: C119.1(+) C120.1 C121.1 C122.1 C123.1 C124.1 C125.1 C126.1 C127.1 C128.1 C129.1 C130.1 C131.1 C132.1 C133.1 L37.2 TP4.1
VA1P1_ADC2: C279.1(+) C280.1 C281.1 C282.1 C283.1 C284.1 C285.1 C286.1 C287.1 C288.1 C289.1 C290.1 C291.1 C292.1 C293.1 L38.2 TP10.1
VD1P1_ADC1: C149.1(+) C150.1 C151.1 C152.1 C153.1 C154.1 C155.1 C156.1 C157.1 C158.1 C159.1 C160.1 L39.2 TP6.1
VD1P1_ADC2: C309.1(+) C310.1 C311.1 C312.1 C313.1 C314.1 C315.1 C316.1 C317.1 C318.1 C319.1 C320.1 L40.2 TP12.1
3P5_VIN: C594.1 U44.12(BIAS) ; port 3P5_VIN
LDO_PG_1P9V: R389.1 ; port LDO_PG_1P9V
PG_3P3V: R388.2 ; port PG_3P3V
NetC364_1: C364.1 C537.1 L88.1 U42.1(EN) U42.2(VIN)
NetC538_1: C538.1 L58.2 R501.2 R502.1 R503.2 TP25.1 U42.4(VOUT) U42.5(VOUT) U43.1
NetC544_2: C544.2 U42.8(SS/TR)
NetC587_1: C587.1 C588.1 C589.1 L58.1 R415.1 TP83.1 U44.15(IN) U44.16(IN) U44.17(IN)
NetC590_1: C590.1 C593.1 R505.1 R506.2 R618.1 U44.1(OUT) U44.19(OUT) U44.20(OUT)
NetC593_2: C593.2 U44.3(FB)
NetC595_1: C595.1 U44.13(NR/SS)
NetR388_1: R388.1 R389.2 R415.2 U44.14(EN)
NetR501_1: R501.1 R502.2 R504.2 U42.6(FB)
NetR503_1: R503.1 U42.7(PG)
NetR505_2: R505.2 TP78.1 U44.4(PG)
NetR506_1: R506.1 U44.2(SNS)
NetR507_2: R507.2 U44.11(1.6_V)
NetR508_2: R508.2 U44.10(800_mV)
NetR509_2: R509.2 U44.9(400_mV)
NetR510_2: R510.2 U44.7(200_mV)
NetR511_2: R511.2 U44.6(100_mV)
NetR512_2: R512.2 U44.5(50_mV)

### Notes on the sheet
- +1.1V  POWER RAIL
- Fsw = 2 MHz
- Build on TIDA-01022-E3 PCB and power solution used from TIDA-01027

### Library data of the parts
C119 C149 C279 C309 = 293D106X0010B2TE3: as C134 on sheet TIDA-01022-E3_Power1
C120-C131 C150-C158 C280-C291 C310-C318 = GRM033C71A104KE14D: as C135 on sheet TIDA-01022-E3_Power1
C132 C133 C159 C160 C292 C293 C319 C320 = C1608X5R1A105K080AC: as C476 on sheet TIDA-01022-E3_FMC+CONN2_1
C364 = GRM1555C1H471JA01D: as C355 on sheet TIDA-01022-E3_Power1
C535 C536 C542 C543 = 885012206095: as C532-C534 on sheet TIDA-01022-E3_Power1
C537 C539-C541 = C3216X7R1E106M160AE: as C494 on sheet TIDA-01022-E3_Power1
C538 = JMK212BJ226MG-T: as C495 on sheet TIDA-01022-E3_Power1
C544 = GRM1885C1H332JA01D: as C501 on sheet TIDA-01022-E3_Power1
C587 C588 C594 = GRM21BR61C106KE15L: as C516 on sheet TIDA-01022-E3_Power1
C589 C590 = GRM219R60G476ME44D: as C518 on sheet TIDA-01022-E3_Power1
C593 C595 = GRM188R71H103KA01D: as C522 on sheet TIDA-01022-E3_Power1
L37-L40 L88 = BLM41PG102SN1L: as L35 on sheet TIDA-01022-E3_Power1
L58 = WE-CBF, 74279252: as L57 on sheet TIDA-01022-E3_Power1
R181 = CRCW12060000Z0EA: as R174 on sheet TIDA-01022-E3_Power1
R388 R389 R415 = CRCW06030000Z0EA: as R222 on sheet TIDA-01022-E3_Power1
R501 = CRCW04023K24FKED: RES, 3.24 k, 1%, 0.063 W, 0402; Manufacturer: Vishay-Dale; CompType: Resistor; Value: 3.24k; Res_ohm: 3240; Value_Code: 3k24; Tolerance_%: 1; Power_W: 0.063; Value2: 0.063W; VDC_V: 50; TempCo: 100 ppm/C; SizeArea_mm2: 0.5; SizeZ_mm: 0.6; EIA_Code: E96; U/M: EA; AEC Category: Q200
R502 = CRCW04026K34FKED: RES, 6.34 k, 1%, 0.063 W, 0402; Manufacturer: Vishay-Dale; CompType: Resistor; Value: 6.34k; Res_ohm: 6340; Value_Code: 6k34; Tolerance_%: 1; Power_W: 0.063; Value2: 0.063W; VDC_V: 50; TempCo: 100 ppm/C; SizeArea_mm2: 0.5; SizeZ_mm: 0.6; EIA_Code: E96; U/M: EA; AEC Category: Q200
R503 = CRCW0402100KFKED: as R489 on sheet TIDA-01022-E3_Power1
R504 = CRCW04029K09FKED: RES, 9.09 k, 1%, 0.063 W, 0402; Manufacturer: Vishay-Dale; CompType: Resistor; Value: 9.09k; Res_ohm: 9090; Value_Code: 9k09; Tolerance_%: 1; Power_W: 0.063; Value2: 0.063W; VDC_V: 50; TempCo: 100 ppm/C; SizeArea_mm2: 0.5; SizeZ_mm: 0.6; EIA_Code: E96; U/M: EA; AEC Category: Q200
R505 = CRCW060310K0FKEA: as R486 on sheet TIDA-01022-E3_Power1
R506 = CRCW06030000Z0EA: as R494 on sheet TIDA-01022-E3_Power1
R507-R512 = CRCW04020000Z0ED: as R479 on sheet TIDA-01022-E3_FMC+CONN2_1
R618 = CRCW12060000Z0EA: as R614 on sheet TIDA-01022-E3_Power1
TP4 TP10 TP78 = TP-025-SMT: as TP5 on sheet TIDA-01022-E3_Power1
TP6 TP12 = 5000: as TP23 on sheet TIDA-01022-E3_Power1
TP25 TP26 = 5000: as 3P3V_RX2 on sheet TIDA-01022-E3_FMC+CONN2_1
TP83 = 5015: as TP77 on sheet TIDA-01022-E3_Power1
U42 = TPS82130SILR: as U39 on sheet TIDA-01022-E3_Power1
U43 = NFM31PC276B0J3L: as U40 on sheet TIDA-01022-E3_Power1
U44 = TPS7A8400RGRR: as U41 on sheet TIDA-01022-E3_Power1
